VERSION 5.8 ;
BUSBITCHARS "[]" ;
DIVIDERCHAR "/" ;
UNITS
    DATABASE MICRONS 1000 ;
END UNITS

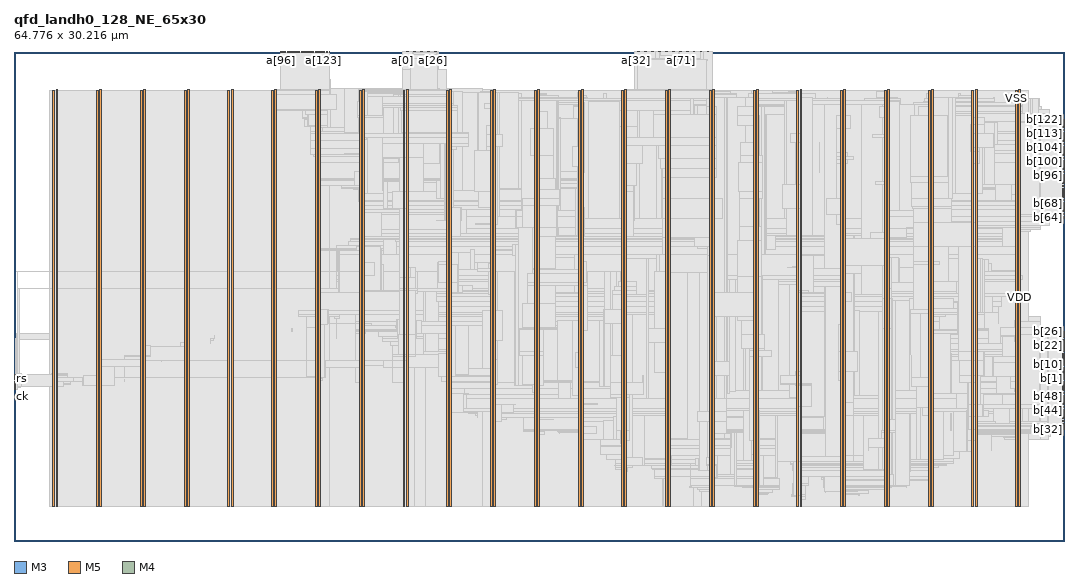
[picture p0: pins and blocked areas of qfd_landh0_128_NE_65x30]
MACRO qfd_landh0_128_NE_65x30
  FOREIGN qfd_landh0_128_NE_65x30 0 0 ;
  CLASS BLOCK ;
  SIZE 64.776 BY 30.216 ;
  PIN a[0]
    DIRECTION INPUT ;
    USE SIGNAL ;
    PORT
      LAYER M3 ;
        RECT  23.94 30.179 23.958 30.216 ;
    END
  END a[0]
  PIN a[100]
    DIRECTION INPUT ;
    USE SIGNAL ;
    PORT
      LAYER M5 ;
        RECT  16.848 30.132 16.872 30.216 ;
    END
  END a[100]
  PIN a[101]
    DIRECTION INPUT ;
    USE SIGNAL ;
    PORT
      LAYER M5 ;
        RECT  16.944 30.132 16.968 30.216 ;
    END
  END a[101]
  PIN a[102]
    DIRECTION INPUT ;
    USE SIGNAL ;
    PORT
      LAYER M5 ;
        RECT  17.04 30.132 17.064 30.216 ;
    END
  END a[102]
  PIN a[103]
    DIRECTION INPUT ;
    USE SIGNAL ;
    PORT
      LAYER M5 ;
        RECT  17.136 30.132 17.16 30.216 ;
    END
  END a[103]
  PIN a[104]
    DIRECTION INPUT ;
    USE SIGNAL ;
    PORT
      LAYER M5 ;
        RECT  17.232 30.132 17.256 30.216 ;
    END
  END a[104]
  PIN a[105]
    DIRECTION INPUT ;
    USE SIGNAL ;
    PORT
      LAYER M5 ;
        RECT  17.328 30.132 17.352 30.216 ;
    END
  END a[105]
  PIN a[106]
    DIRECTION INPUT ;
    USE SIGNAL ;
    PORT
      LAYER M5 ;
        RECT  17.424 30.132 17.448 30.216 ;
    END
  END a[106]
  PIN a[107]
    DIRECTION INPUT ;
    USE SIGNAL ;
    PORT
      LAYER M5 ;
        RECT  17.52 30.132 17.544 30.216 ;
    END
  END a[107]
  PIN a[108]
    DIRECTION INPUT ;
    USE SIGNAL ;
    PORT
      LAYER M5 ;
        RECT  17.616 30.132 17.64 30.216 ;
    END
  END a[108]
  PIN a[109]
    DIRECTION INPUT ;
    USE SIGNAL ;
    PORT
      LAYER M5 ;
        RECT  17.712 30.132 17.736 30.216 ;
    END
  END a[109]
  PIN a[10]
    DIRECTION INPUT ;
    USE SIGNAL ;
    PORT
      LAYER M3 ;
        RECT  24.66 30.179 24.678 30.216 ;
    END
  END a[10]
  PIN a[110]
    DIRECTION INPUT ;
    USE SIGNAL ;
    PORT
      LAYER M5 ;
        RECT  17.808 30.132 17.832 30.216 ;
    END
  END a[110]
  PIN a[111]
    DIRECTION INPUT ;
    USE SIGNAL ;
    PORT
      LAYER M5 ;
        RECT  17.904 30.132 17.928 30.216 ;
    END
  END a[111]
  PIN a[112]
    DIRECTION INPUT ;
    USE SIGNAL ;
    PORT
      LAYER M5 ;
        RECT  18 30.132 18.024 30.216 ;
    END
  END a[112]
  PIN a[113]
    DIRECTION INPUT ;
    USE SIGNAL ;
    PORT
      LAYER M5 ;
        RECT  18.096 30.132 18.12 30.216 ;
    END
  END a[113]
  PIN a[114]
    DIRECTION INPUT ;
    USE SIGNAL ;
    PORT
      LAYER M5 ;
        RECT  18.192 30.132 18.216 30.216 ;
    END
  END a[114]
  PIN a[115]
    DIRECTION INPUT ;
    USE SIGNAL ;
    PORT
      LAYER M5 ;
        RECT  18.288 30.132 18.312 30.216 ;
    END
  END a[115]
  PIN a[116]
    DIRECTION INPUT ;
    USE SIGNAL ;
    PORT
      LAYER M5 ;
        RECT  18.384 30.132 18.408 30.216 ;
    END
  END a[116]
  PIN a[117]
    DIRECTION INPUT ;
    USE SIGNAL ;
    PORT
      LAYER M5 ;
        RECT  18.48 30.132 18.504 30.216 ;
    END
  END a[117]
  PIN a[118]
    DIRECTION INPUT ;
    USE SIGNAL ;
    PORT
      LAYER M5 ;
        RECT  18.576 30.132 18.6 30.216 ;
    END
  END a[118]
  PIN a[119]
    DIRECTION INPUT ;
    USE SIGNAL ;
    PORT
      LAYER M5 ;
        RECT  18.672 30.132 18.696 30.216 ;
    END
  END a[119]
  PIN a[11]
    DIRECTION INPUT ;
    USE SIGNAL ;
    PORT
      LAYER M3 ;
        RECT  24.732 30.179 24.75 30.216 ;
    END
  END a[11]
  PIN a[120]
    DIRECTION INPUT ;
    USE SIGNAL ;
    PORT
      LAYER M5 ;
        RECT  18.768 30.132 18.792 30.216 ;
    END
  END a[120]
  PIN a[121]
    DIRECTION INPUT ;
    USE SIGNAL ;
    PORT
      LAYER M5 ;
        RECT  18.864 30.132 18.888 30.216 ;
    END
  END a[121]
  PIN a[122]
    DIRECTION INPUT ;
    USE SIGNAL ;
    PORT
      LAYER M5 ;
        RECT  18.96 30.132 18.984 30.216 ;
    END
  END a[122]
  PIN a[123]
    DIRECTION INPUT ;
    USE SIGNAL ;
    PORT
      LAYER M5 ;
        RECT  19.056 30.132 19.08 30.216 ;
    END
  END a[123]
  PIN a[124]
    DIRECTION INPUT ;
    USE SIGNAL ;
    PORT
      LAYER M5 ;
        RECT  19.152 30.132 19.176 30.216 ;
    END
  END a[124]
  PIN a[125]
    DIRECTION INPUT ;
    USE SIGNAL ;
    PORT
      LAYER M5 ;
        RECT  19.248 30.132 19.272 30.216 ;
    END
  END a[125]
  PIN a[126]
    DIRECTION INPUT ;
    USE SIGNAL ;
    PORT
      LAYER M5 ;
        RECT  19.344 30.132 19.368 30.216 ;
    END
  END a[126]
  PIN a[127]
    DIRECTION INPUT ;
    USE SIGNAL ;
    PORT
      LAYER M5 ;
        RECT  19.44 30.132 19.464 30.216 ;
    END
  END a[127]
  PIN a[12]
    DIRECTION INPUT ;
    USE SIGNAL ;
    PORT
      LAYER M3 ;
        RECT  24.804 30.179 24.822 30.216 ;
    END
  END a[12]
  PIN a[13]
    DIRECTION INPUT ;
    USE SIGNAL ;
    PORT
      LAYER M3 ;
        RECT  24.876 30.179 24.894 30.216 ;
    END
  END a[13]
  PIN a[14]
    DIRECTION INPUT ;
    USE SIGNAL ;
    PORT
      LAYER M3 ;
        RECT  24.948 30.179 24.966 30.216 ;
    END
  END a[14]
  PIN a[15]
    DIRECTION INPUT ;
    USE SIGNAL ;
    PORT
      LAYER M3 ;
        RECT  25.02 30.179 25.038 30.216 ;
    END
  END a[15]
  PIN a[16]
    DIRECTION INPUT ;
    USE SIGNAL ;
    PORT
      LAYER M3 ;
        RECT  25.092 30.179 25.11 30.216 ;
    END
  END a[16]
  PIN a[17]
    DIRECTION INPUT ;
    USE SIGNAL ;
    PORT
      LAYER M3 ;
        RECT  25.164 30.179 25.182 30.216 ;
    END
  END a[17]
  PIN a[18]
    DIRECTION INPUT ;
    USE SIGNAL ;
    PORT
      LAYER M3 ;
        RECT  25.236 30.179 25.254 30.216 ;
    END
  END a[18]
  PIN a[19]
    DIRECTION INPUT ;
    USE SIGNAL ;
    PORT
      LAYER M3 ;
        RECT  25.308 30.179 25.326 30.216 ;
    END
  END a[19]
  PIN a[1]
    DIRECTION INPUT ;
    USE SIGNAL ;
    PORT
      LAYER M3 ;
        RECT  24.012 30.179 24.03 30.216 ;
    END
  END a[1]
  PIN a[20]
    DIRECTION INPUT ;
    USE SIGNAL ;
    PORT
      LAYER M3 ;
        RECT  25.38 30.179 25.398 30.216 ;
    END
  END a[20]
  PIN a[21]
    DIRECTION INPUT ;
    USE SIGNAL ;
    PORT
      LAYER M3 ;
        RECT  25.452 30.179 25.47 30.216 ;
    END
  END a[21]
  PIN a[22]
    DIRECTION INPUT ;
    USE SIGNAL ;
    PORT
      LAYER M3 ;
        RECT  25.524 30.179 25.542 30.216 ;
    END
  END a[22]
  PIN a[23]
    DIRECTION INPUT ;
    USE SIGNAL ;
    PORT
      LAYER M3 ;
        RECT  25.596 30.179 25.614 30.216 ;
    END
  END a[23]
  PIN a[24]
    DIRECTION INPUT ;
    USE SIGNAL ;
    PORT
      LAYER M3 ;
        RECT  25.668 30.179 25.686 30.216 ;
    END
  END a[24]
  PIN a[25]
    DIRECTION INPUT ;
    USE SIGNAL ;
    PORT
      LAYER M3 ;
        RECT  25.74 30.179 25.758 30.216 ;
    END
  END a[25]
  PIN a[26]
    DIRECTION INPUT ;
    USE SIGNAL ;
    PORT
      LAYER M3 ;
        RECT  25.812 30.179 25.83 30.216 ;
    END
  END a[26]
  PIN a[27]
    DIRECTION INPUT ;
    USE SIGNAL ;
    PORT
      LAYER M3 ;
        RECT  25.884 30.179 25.902 30.216 ;
    END
  END a[27]
  PIN a[28]
    DIRECTION INPUT ;
    USE SIGNAL ;
    PORT
      LAYER M3 ;
        RECT  25.956 30.179 25.974 30.216 ;
    END
  END a[28]
  PIN a[29]
    DIRECTION INPUT ;
    USE SIGNAL ;
    PORT
      LAYER M3 ;
        RECT  26.028 30.179 26.046 30.216 ;
    END
  END a[29]
  PIN a[2]
    DIRECTION INPUT ;
    USE SIGNAL ;
    PORT
      LAYER M3 ;
        RECT  24.084 30.179 24.102 30.216 ;
    END
  END a[2]
  PIN a[30]
    DIRECTION INPUT ;
    USE SIGNAL ;
    PORT
      LAYER M3 ;
        RECT  26.1 30.179 26.118 30.216 ;
    END
  END a[30]
  PIN a[31]
    DIRECTION INPUT ;
    USE SIGNAL ;
    PORT
      LAYER M3 ;
        RECT  26.172 30.179 26.19 30.216 ;
    END
  END a[31]
  PIN a[32]
    DIRECTION INPUT ;
    USE SIGNAL ;
    PORT
      LAYER M3 ;
        RECT  38.34 30.179 38.358 30.216 ;
    END
  END a[32]
  PIN a[33]
    DIRECTION INPUT ;
    USE SIGNAL ;
    PORT
      LAYER M3 ;
        RECT  38.412 30.179 38.43 30.216 ;
    END
  END a[33]
  PIN a[34]
    DIRECTION INPUT ;
    USE SIGNAL ;
    PORT
      LAYER M3 ;
        RECT  38.484 30.179 38.502 30.216 ;
    END
  END a[34]
  PIN a[35]
    DIRECTION INPUT ;
    USE SIGNAL ;
    PORT
      LAYER M3 ;
        RECT  38.556 30.179 38.574 30.216 ;
    END
  END a[35]
  PIN a[36]
    DIRECTION INPUT ;
    USE SIGNAL ;
    PORT
      LAYER M3 ;
        RECT  38.628 30.179 38.646 30.216 ;
    END
  END a[36]
  PIN a[37]
    DIRECTION INPUT ;
    USE SIGNAL ;
    PORT
      LAYER M3 ;
        RECT  38.7 30.179 38.718 30.216 ;
    END
  END a[37]
  PIN a[38]
    DIRECTION INPUT ;
    USE SIGNAL ;
    PORT
      LAYER M3 ;
        RECT  38.772 30.179 38.79 30.216 ;
    END
  END a[38]
  PIN a[39]
    DIRECTION INPUT ;
    USE SIGNAL ;
    PORT
      LAYER M3 ;
        RECT  38.844 30.179 38.862 30.216 ;
    END
  END a[39]
  PIN a[3]
    DIRECTION INPUT ;
    USE SIGNAL ;
    PORT
      LAYER M3 ;
        RECT  24.156 30.179 24.174 30.216 ;
    END
  END a[3]
  PIN a[40]
    DIRECTION INPUT ;
    USE SIGNAL ;
    PORT
      LAYER M3 ;
        RECT  38.916 30.179 38.934 30.216 ;
    END
  END a[40]
  PIN a[41]
    DIRECTION INPUT ;
    USE SIGNAL ;
    PORT
      LAYER M3 ;
        RECT  38.988 30.179 39.006 30.216 ;
    END
  END a[41]
  PIN a[42]
    DIRECTION INPUT ;
    USE SIGNAL ;
    PORT
      LAYER M3 ;
        RECT  39.06 30.179 39.078 30.216 ;
    END
  END a[42]
  PIN a[43]
    DIRECTION INPUT ;
    USE SIGNAL ;
    PORT
      LAYER M3 ;
        RECT  39.132 30.179 39.15 30.216 ;
    END
  END a[43]
  PIN a[44]
    DIRECTION INPUT ;
    USE SIGNAL ;
    PORT
      LAYER M3 ;
        RECT  39.204 30.179 39.222 30.216 ;
    END
  END a[44]
  PIN a[45]
    DIRECTION INPUT ;
    USE SIGNAL ;
    PORT
      LAYER M3 ;
        RECT  39.276 30.179 39.294 30.216 ;
    END
  END a[45]
  PIN a[46]
    DIRECTION INPUT ;
    USE SIGNAL ;
    PORT
      LAYER M3 ;
        RECT  39.348 30.179 39.366 30.216 ;
    END
  END a[46]
  PIN a[47]
    DIRECTION INPUT ;
    USE SIGNAL ;
    PORT
      LAYER M3 ;
        RECT  39.42 30.179 39.438 30.216 ;
    END
  END a[47]
  PIN a[48]
    DIRECTION INPUT ;
    USE SIGNAL ;
    PORT
      LAYER M3 ;
        RECT  39.492 30.179 39.51 30.216 ;
    END
  END a[48]
  PIN a[49]
    DIRECTION INPUT ;
    USE SIGNAL ;
    PORT
      LAYER M3 ;
        RECT  39.564 30.179 39.582 30.216 ;
    END
  END a[49]
  PIN a[4]
    DIRECTION INPUT ;
    USE SIGNAL ;
    PORT
      LAYER M3 ;
        RECT  24.228 30.179 24.246 30.216 ;
    END
  END a[4]
  PIN a[50]
    DIRECTION INPUT ;
    USE SIGNAL ;
    PORT
      LAYER M3 ;
        RECT  39.636 30.179 39.654 30.216 ;
    END
  END a[50]
  PIN a[51]
    DIRECTION INPUT ;
    USE SIGNAL ;
    PORT
      LAYER M3 ;
        RECT  39.708 30.179 39.726 30.216 ;
    END
  END a[51]
  PIN a[52]
    DIRECTION INPUT ;
    USE SIGNAL ;
    PORT
      LAYER M3 ;
        RECT  39.78 30.179 39.798 30.216 ;
    END
  END a[52]
  PIN a[53]
    DIRECTION INPUT ;
    USE SIGNAL ;
    PORT
      LAYER M3 ;
        RECT  39.852 30.179 39.87 30.216 ;
    END
  END a[53]
  PIN a[54]
    DIRECTION INPUT ;
    USE SIGNAL ;
    PORT
      LAYER M3 ;
        RECT  39.924 30.179 39.942 30.216 ;
    END
  END a[54]
  PIN a[55]
    DIRECTION INPUT ;
    USE SIGNAL ;
    PORT
      LAYER M3 ;
        RECT  39.996 30.179 40.014 30.216 ;
    END
  END a[55]
  PIN a[56]
    DIRECTION INPUT ;
    USE SIGNAL ;
    PORT
      LAYER M3 ;
        RECT  40.068 30.179 40.086 30.216 ;
    END
  END a[56]
  PIN a[57]
    DIRECTION INPUT ;
    USE SIGNAL ;
    PORT
      LAYER M3 ;
        RECT  40.14 30.179 40.158 30.216 ;
    END
  END a[57]
  PIN a[58]
    DIRECTION INPUT ;
    USE SIGNAL ;
    PORT
      LAYER M3 ;
        RECT  40.212 30.179 40.23 30.216 ;
    END
  END a[58]
  PIN a[59]
    DIRECTION INPUT ;
    USE SIGNAL ;
    PORT
      LAYER M3 ;
        RECT  40.284 30.179 40.302 30.216 ;
    END
  END a[59]
  PIN a[5]
    DIRECTION INPUT ;
    USE SIGNAL ;
    PORT
      LAYER M3 ;
        RECT  24.3 30.179 24.318 30.216 ;
    END
  END a[5]
  PIN a[60]
    DIRECTION INPUT ;
    USE SIGNAL ;
    PORT
      LAYER M3 ;
        RECT  40.356 30.179 40.374 30.216 ;
    END
  END a[60]
  PIN a[61]
    DIRECTION INPUT ;
    USE SIGNAL ;
    PORT
      LAYER M3 ;
        RECT  40.428 30.179 40.446 30.216 ;
    END
  END a[61]
  PIN a[62]
    DIRECTION INPUT ;
    USE SIGNAL ;
    PORT
      LAYER M3 ;
        RECT  40.5 30.179 40.518 30.216 ;
    END
  END a[62]
  PIN a[63]
    DIRECTION INPUT ;
    USE SIGNAL ;
    PORT
      LAYER M3 ;
        RECT  40.572 30.179 40.59 30.216 ;
    END
  END a[63]
  PIN a[64]
    DIRECTION INPUT ;
    USE SIGNAL ;
    PORT
      LAYER M3 ;
        RECT  40.644 30.179 40.662 30.216 ;
    END
  END a[64]
  PIN a[65]
    DIRECTION INPUT ;
    USE SIGNAL ;
    PORT
      LAYER M3 ;
        RECT  40.716 30.179 40.734 30.216 ;
    END
  END a[65]
  PIN a[66]
    DIRECTION INPUT ;
    USE SIGNAL ;
    PORT
      LAYER M3 ;
        RECT  40.788 30.179 40.806 30.216 ;
    END
  END a[66]
  PIN a[67]
    DIRECTION INPUT ;
    USE SIGNAL ;
    PORT
      LAYER M3 ;
        RECT  40.86 30.179 40.878 30.216 ;
    END
  END a[67]
  PIN a[68]
    DIRECTION INPUT ;
    USE SIGNAL ;
    PORT
      LAYER M3 ;
        RECT  40.932 30.179 40.95 30.216 ;
    END
  END a[68]
  PIN a[69]
    DIRECTION INPUT ;
    USE SIGNAL ;
    PORT
      LAYER M3 ;
        RECT  41.004 30.179 41.022 30.216 ;
    END
  END a[69]
  PIN a[6]
    DIRECTION INPUT ;
    USE SIGNAL ;
    PORT
      LAYER M3 ;
        RECT  24.372 30.179 24.39 30.216 ;
    END
  END a[6]
  PIN a[70]
    DIRECTION INPUT ;
    USE SIGNAL ;
    PORT
      LAYER M3 ;
        RECT  41.076 30.179 41.094 30.216 ;
    END
  END a[70]
  PIN a[71]
    DIRECTION INPUT ;
    USE SIGNAL ;
    PORT
      LAYER M3 ;
        RECT  41.148 30.179 41.166 30.216 ;
    END
  END a[71]
  PIN a[72]
    DIRECTION INPUT ;
    USE SIGNAL ;
    PORT
      LAYER M3 ;
        RECT  41.22 30.179 41.238 30.216 ;
    END
  END a[72]
  PIN a[73]
    DIRECTION INPUT ;
    USE SIGNAL ;
    PORT
      LAYER M3 ;
        RECT  41.292 30.179 41.31 30.216 ;
    END
  END a[73]
  PIN a[74]
    DIRECTION INPUT ;
    USE SIGNAL ;
    PORT
      LAYER M3 ;
        RECT  41.364 30.179 41.382 30.216 ;
    END
  END a[74]
  PIN a[75]
    DIRECTION INPUT ;
    USE SIGNAL ;
    PORT
      LAYER M3 ;
        RECT  41.436 30.179 41.454 30.216 ;
    END
  END a[75]
  PIN a[76]
    DIRECTION INPUT ;
    USE SIGNAL ;
    PORT
      LAYER M3 ;
        RECT  41.508 30.179 41.526 30.216 ;
    END
  END a[76]
  PIN a[77]
    DIRECTION INPUT ;
    USE SIGNAL ;
    PORT
      LAYER M3 ;
        RECT  41.58 30.179 41.598 30.216 ;
    END
  END a[77]
  PIN a[78]
    DIRECTION INPUT ;
    USE SIGNAL ;
    PORT
      LAYER M3 ;
        RECT  41.652 30.179 41.67 30.216 ;
    END
  END a[78]
  PIN a[79]
    DIRECTION INPUT ;
    USE SIGNAL ;
    PORT
      LAYER M3 ;
        RECT  41.724 30.179 41.742 30.216 ;
    END
  END a[79]
  PIN a[7]
    DIRECTION INPUT ;
    USE SIGNAL ;
    PORT
      LAYER M3 ;
        RECT  24.444 30.179 24.462 30.216 ;
    END
  END a[7]
  PIN a[80]
    DIRECTION INPUT ;
    USE SIGNAL ;
    PORT
      LAYER M3 ;
        RECT  41.796 30.179 41.814 30.216 ;
    END
  END a[80]
  PIN a[81]
    DIRECTION INPUT ;
    USE SIGNAL ;
    PORT
      LAYER M3 ;
        RECT  41.868 30.179 41.886 30.216 ;
    END
  END a[81]
  PIN a[82]
    DIRECTION INPUT ;
    USE SIGNAL ;
    PORT
      LAYER M3 ;
        RECT  41.94 30.179 41.958 30.216 ;
    END
  END a[82]
  PIN a[83]
    DIRECTION INPUT ;
    USE SIGNAL ;
    PORT
      LAYER M3 ;
        RECT  42.012 30.179 42.03 30.216 ;
    END
  END a[83]
  PIN a[84]
    DIRECTION INPUT ;
    USE SIGNAL ;
    PORT
      LAYER M3 ;
        RECT  42.084 30.179 42.102 30.216 ;
    END
  END a[84]
  PIN a[85]
    DIRECTION INPUT ;
    USE SIGNAL ;
    PORT
      LAYER M3 ;
        RECT  42.156 30.179 42.174 30.216 ;
    END
  END a[85]
  PIN a[86]
    DIRECTION INPUT ;
    USE SIGNAL ;
    PORT
      LAYER M3 ;
        RECT  42.228 30.179 42.246 30.216 ;
    END
  END a[86]
  PIN a[87]
    DIRECTION INPUT ;
    USE SIGNAL ;
    PORT
      LAYER M3 ;
        RECT  42.3 30.179 42.318 30.216 ;
    END
  END a[87]
  PIN a[88]
    DIRECTION INPUT ;
    USE SIGNAL ;
    PORT
      LAYER M3 ;
        RECT  42.372 30.179 42.39 30.216 ;
    END
  END a[88]
  PIN a[89]
    DIRECTION INPUT ;
    USE SIGNAL ;
    PORT
      LAYER M3 ;
        RECT  42.444 30.179 42.462 30.216 ;
    END
  END a[89]
  PIN a[8]
    DIRECTION INPUT ;
    USE SIGNAL ;
    PORT
      LAYER M3 ;
        RECT  24.516 30.179 24.534 30.216 ;
    END
  END a[8]
  PIN a[90]
    DIRECTION INPUT ;
    USE SIGNAL ;
    PORT
      LAYER M3 ;
        RECT  42.516 30.179 42.534 30.216 ;
    END
  END a[90]
  PIN a[91]
    DIRECTION INPUT ;
    USE SIGNAL ;
    PORT
      LAYER M3 ;
        RECT  42.588 30.179 42.606 30.216 ;
    END
  END a[91]
  PIN a[92]
    DIRECTION INPUT ;
    USE SIGNAL ;
    PORT
      LAYER M3 ;
        RECT  42.66 30.179 42.678 30.216 ;
    END
  END a[92]
  PIN a[93]
    DIRECTION INPUT ;
    USE SIGNAL ;
    PORT
      LAYER M3 ;
        RECT  42.732 30.179 42.75 30.216 ;
    END
  END a[93]
  PIN a[94]
    DIRECTION INPUT ;
    USE SIGNAL ;
    PORT
      LAYER M3 ;
        RECT  42.804 30.179 42.822 30.216 ;
    END
  END a[94]
  PIN a[95]
    DIRECTION INPUT ;
    USE SIGNAL ;
    PORT
      LAYER M3 ;
        RECT  42.876 30.179 42.894 30.216 ;
    END
  END a[95]
  PIN a[96]
    DIRECTION INPUT ;
    USE SIGNAL ;
    PORT
      LAYER M5 ;
        RECT  16.464 30.132 16.488 30.216 ;
    END
  END a[96]
  PIN a[97]
    DIRECTION INPUT ;
    USE SIGNAL ;
    PORT
      LAYER M5 ;
        RECT  16.56 30.132 16.584 30.216 ;
    END
  END a[97]
  PIN a[98]
    DIRECTION INPUT ;
    USE SIGNAL ;
    PORT
      LAYER M5 ;
        RECT  16.656 30.132 16.68 30.216 ;
    END
  END a[98]
  PIN a[99]
    DIRECTION INPUT ;
    USE SIGNAL ;
    PORT
      LAYER M5 ;
        RECT  16.752 30.132 16.776 30.216 ;
    END
  END a[99]
  PIN a[9]
    DIRECTION INPUT ;
    USE SIGNAL ;
    PORT
      LAYER M3 ;
        RECT  24.588 30.179 24.606 30.216 ;
    END
  END a[9]
  PIN b[0]
    DIRECTION OUTPUT ;
    USE SIGNAL ;
    PORT
      LAYER M4 ;
        RECT  64.692 9.936 64.776 9.96 ;
    END
  END b[0]
  PIN b[100]
    DIRECTION OUTPUT ;
    USE SIGNAL ;
    PORT
      LAYER M4 ;
        RECT  64.692 23.376 64.776 23.4 ;
    END
  END b[100]
  PIN b[101]
    DIRECTION OUTPUT ;
    USE SIGNAL ;
    PORT
      LAYER M4 ;
        RECT  64.692 23.472 64.776 23.496 ;
    END
  END b[101]
  PIN b[102]
    DIRECTION OUTPUT ;
    USE SIGNAL ;
    PORT
      LAYER M4 ;
        RECT  64.692 23.568 64.776 23.592 ;
    END
  END b[102]
  PIN b[103]
    DIRECTION OUTPUT ;
    USE SIGNAL ;
    PORT
      LAYER M4 ;
        RECT  64.692 23.664 64.776 23.688 ;
    END
  END b[103]
  PIN b[104]
    DIRECTION OUTPUT ;
    USE SIGNAL ;
    PORT
      LAYER M4 ;
        RECT  64.692 23.76 64.776 23.784 ;
    END
  END b[104]
  PIN b[105]
    DIRECTION OUTPUT ;
    USE SIGNAL ;
    PORT
      LAYER M4 ;
        RECT  64.692 23.856 64.776 23.88 ;
    END
  END b[105]
  PIN b[106]
    DIRECTION OUTPUT ;
    USE SIGNAL ;
    PORT
      LAYER M4 ;
        RECT  64.692 23.952 64.776 23.976 ;
    END
  END b[106]
  PIN b[107]
    DIRECTION OUTPUT ;
    USE SIGNAL ;
    PORT
      LAYER M4 ;
        RECT  64.692 24.048 64.776 24.072 ;
    END
  END b[107]
  PIN b[108]
    DIRECTION OUTPUT ;
    USE SIGNAL ;
    PORT
      LAYER M4 ;
        RECT  64.692 24.144 64.776 24.168 ;
    END
  END b[108]
  PIN b[109]
    DIRECTION OUTPUT ;
    USE SIGNAL ;
    PORT
      LAYER M4 ;
        RECT  64.692 24.24 64.776 24.264 ;
    END
  END b[109]
  PIN b[10]
    DIRECTION OUTPUT ;
    USE SIGNAL ;
    PORT
      LAYER M4 ;
        RECT  64.692 10.896 64.776 10.92 ;
    END
  END b[10]
  PIN b[110]
    DIRECTION OUTPUT ;
    USE SIGNAL ;
    PORT
      LAYER M4 ;
        RECT  64.692 24.336 64.776 24.36 ;
    END
  END b[110]
  PIN b[111]
    DIRECTION OUTPUT ;
    USE SIGNAL ;
    PORT
      LAYER M4 ;
        RECT  64.692 24.432 64.776 24.456 ;
    END
  END b[111]
  PIN b[112]
    DIRECTION OUTPUT ;
    USE SIGNAL ;
    PORT
      LAYER M4 ;
        RECT  64.692 24.528 64.776 24.552 ;
    END
  END b[112]
  PIN b[113]
    DIRECTION OUTPUT ;
    USE SIGNAL ;
    PORT
      LAYER M4 ;
        RECT  64.692 24.624 64.776 24.648 ;
    END
  END b[113]
  PIN b[114]
    DIRECTION OUTPUT ;
    USE SIGNAL ;
    PORT
      LAYER M4 ;
        RECT  64.692 24.72 64.776 24.744 ;
    END
  END b[114]
  PIN b[115]
    DIRECTION OUTPUT ;
    USE SIGNAL ;
    PORT
      LAYER M4 ;
        RECT  64.692 24.816 64.776 24.84 ;
    END
  END b[115]
  PIN b[116]
    DIRECTION OUTPUT ;
    USE SIGNAL ;
    PORT
      LAYER M4 ;
        RECT  64.692 24.912 64.776 24.936 ;
    END
  END b[116]
  PIN b[117]
    DIRECTION OUTPUT ;
    USE SIGNAL ;
    PORT
      LAYER M4 ;
        RECT  64.692 25.008 64.776 25.032 ;
    END
  END b[117]
  PIN b[118]
    DIRECTION OUTPUT ;
    USE SIGNAL ;
    PORT
      LAYER M4 ;
        RECT  64.692 25.104 64.776 25.128 ;
    END
  END b[118]
  PIN b[119]
    DIRECTION OUTPUT ;
    USE SIGNAL ;
    PORT
      LAYER M4 ;
        RECT  64.692 25.2 64.776 25.224 ;
    END
  END b[119]
  PIN b[11]
    DIRECTION OUTPUT ;
    USE SIGNAL ;
    PORT
      LAYER M4 ;
        RECT  64.692 10.992 64.776 11.016 ;
    END
  END b[11]
  PIN b[120]
    DIRECTION OUTPUT ;
    USE SIGNAL ;
    PORT
      LAYER M4 ;
        RECT  64.692 25.296 64.776 25.32 ;
    END
  END b[120]
  PIN b[121]
    DIRECTION OUTPUT ;
    USE SIGNAL ;
    PORT
      LAYER M4 ;
        RECT  64.692 25.392 64.776 25.416 ;
    END
  END b[121]
  PIN b[122]
    DIRECTION OUTPUT ;
    USE SIGNAL ;
    PORT
      LAYER M4 ;
        RECT  64.692 25.488 64.776 25.512 ;
    END
  END b[122]
  PIN b[123]
    DIRECTION OUTPUT ;
    USE SIGNAL ;
    PORT
      LAYER M4 ;
        RECT  64.692 25.584 64.776 25.608 ;
    END
  END b[123]
  PIN b[124]
    DIRECTION OUTPUT ;
    USE SIGNAL ;
    PORT
      LAYER M4 ;
        RECT  64.692 25.68 64.776 25.704 ;
    END
  END b[124]
  PIN b[125]
    DIRECTION OUTPUT ;
    USE SIGNAL ;
    PORT
      LAYER M4 ;
        RECT  64.692 25.776 64.776 25.8 ;
    END
  END b[125]
  PIN b[126]
    DIRECTION OUTPUT ;
    USE SIGNAL ;
    PORT
      LAYER M4 ;
        RECT  64.692 25.872 64.776 25.896 ;
    END
  END b[126]
  PIN b[127]
    DIRECTION OUTPUT ;
    USE SIGNAL ;
    PORT
      LAYER M4 ;
        RECT  64.692 25.968 64.776 25.992 ;
    END
  END b[127]
  PIN b[12]
    DIRECTION OUTPUT ;
    USE SIGNAL ;
    PORT
      LAYER M4 ;
        RECT  64.692 11.088 64.776 11.112 ;
    END
  END b[12]
  PIN b[13]
    DIRECTION OUTPUT ;
    USE SIGNAL ;
    PORT
      LAYER M4 ;
        RECT  64.692 11.184 64.776 11.208 ;
    END
  END b[13]
  PIN b[14]
    DIRECTION OUTPUT ;
    USE SIGNAL ;
    PORT
      LAYER M4 ;
        RECT  64.692 11.28 64.776 11.304 ;
    END
  END b[14]
  PIN b[15]
    DIRECTION OUTPUT ;
    USE SIGNAL ;
    PORT
      LAYER M4 ;
        RECT  64.692 11.376 64.776 11.4 ;
    END
  END b[15]
  PIN b[16]
    DIRECTION OUTPUT ;
    USE SIGNAL ;
    PORT
      LAYER M4 ;
        RECT  64.692 11.472 64.776 11.496 ;
    END
  END b[16]
  PIN b[17]
    DIRECTION OUTPUT ;
    USE SIGNAL ;
    PORT
      LAYER M4 ;
        RECT  64.692 11.568 64.776 11.592 ;
    END
  END b[17]
  PIN b[18]
    DIRECTION OUTPUT ;
    USE SIGNAL ;
    PORT
      LAYER M4 ;
        RECT  64.692 11.664 64.776 11.688 ;
    END
  END b[18]
  PIN b[19]
    DIRECTION OUTPUT ;
    USE SIGNAL ;
    PORT
      LAYER M4 ;
        RECT  64.692 11.76 64.776 11.784 ;
    END
  END b[19]
  PIN b[1]
    DIRECTION OUTPUT ;
    USE SIGNAL ;
    PORT
      LAYER M4 ;
        RECT  64.692 10.032 64.776 10.056 ;
    END
  END b[1]
  PIN b[20]
    DIRECTION OUTPUT ;
    USE SIGNAL ;
    PORT
      LAYER M4 ;
        RECT  64.692 11.856 64.776 11.88 ;
    END
  END b[20]
  PIN b[21]
    DIRECTION OUTPUT ;
    USE SIGNAL ;
    PORT
      LAYER M4 ;
        RECT  64.692 11.952 64.776 11.976 ;
    END
  END b[21]
  PIN b[22]
    DIRECTION OUTPUT ;
    USE SIGNAL ;
    PORT
      LAYER M4 ;
        RECT  64.692 12.048 64.776 12.072 ;
    END
  END b[22]
  PIN b[23]
    DIRECTION OUTPUT ;
    USE SIGNAL ;
    PORT
      LAYER M4 ;
        RECT  64.692 12.144 64.776 12.168 ;
    END
  END b[23]
  PIN b[24]
    DIRECTION OUTPUT ;
    USE SIGNAL ;
    PORT
      LAYER M4 ;
        RECT  64.692 12.24 64.776 12.264 ;
    END
  END b[24]
  PIN b[25]
    DIRECTION OUTPUT ;
    USE SIGNAL ;
    PORT
      LAYER M4 ;
        RECT  64.692 12.336 64.776 12.36 ;
    END
  END b[25]
  PIN b[26]
    DIRECTION OUTPUT ;
    USE SIGNAL ;
    PORT
      LAYER M4 ;
        RECT  64.692 12.432 64.776 12.456 ;
    END
  END b[26]
  PIN b[27]
    DIRECTION OUTPUT ;
    USE SIGNAL ;
    PORT
      LAYER M4 ;
        RECT  64.692 12.528 64.776 12.552 ;
    END
  END b[27]
  PIN b[28]
    DIRECTION OUTPUT ;
    USE SIGNAL ;
    PORT
      LAYER M4 ;
        RECT  64.692 12.624 64.776 12.648 ;
    END
  END b[28]
  PIN b[29]
    DIRECTION OUTPUT ;
    USE SIGNAL ;
    PORT
      LAYER M4 ;
        RECT  64.692 12.72 64.776 12.744 ;
    END
  END b[29]
  PIN b[2]
    DIRECTION OUTPUT ;
    USE SIGNAL ;
    PORT
      LAYER M4 ;
        RECT  64.692 10.128 64.776 10.152 ;
    END
  END b[2]
  PIN b[30]
    DIRECTION OUTPUT ;
    USE SIGNAL ;
    PORT
      LAYER M4 ;
        RECT  64.692 12.816 64.776 12.84 ;
    END
  END b[30]
  PIN b[31]
    DIRECTION OUTPUT ;
    USE SIGNAL ;
    PORT
      LAYER M4 ;
        RECT  64.692 12.912 64.776 12.936 ;
    END
  END b[31]
  PIN b[32]
    DIRECTION OUTPUT ;
    USE SIGNAL ;
    PORT
      LAYER M4 ;
        RECT  64.692 6.864 64.776 6.888 ;
    END
  END b[32]
  PIN b[33]
    DIRECTION OUTPUT ;
    USE SIGNAL ;
    PORT
      LAYER M4 ;
        RECT  64.692 6.96 64.776 6.984 ;
    END
  END b[33]
  PIN b[34]
    DIRECTION OUTPUT ;
    USE SIGNAL ;
    PORT
      LAYER M4 ;
        RECT  64.692 7.056 64.776 7.08 ;
    END
  END b[34]
  PIN b[35]
    DIRECTION OUTPUT ;
    USE SIGNAL ;
    PORT
      LAYER M4 ;
        RECT  64.692 7.152 64.776 7.176 ;
    END
  END b[35]
  PIN b[36]
    DIRECTION OUTPUT ;
    USE SIGNAL ;
    PORT
      LAYER M4 ;
        RECT  64.692 7.248 64.776 7.272 ;
    END
  END b[36]
  PIN b[37]
    DIRECTION OUTPUT ;
    USE SIGNAL ;
    PORT
      LAYER M4 ;
        RECT  64.692 7.344 64.776 7.368 ;
    END
  END b[37]
  PIN b[38]
    DIRECTION OUTPUT ;
    USE SIGNAL ;
    PORT
      LAYER M4 ;
        RECT  64.692 7.44 64.776 7.464 ;
    END
  END b[38]
  PIN b[39]
    DIRECTION OUTPUT ;
    USE SIGNAL ;
    PORT
      LAYER M4 ;
        RECT  64.692 7.536 64.776 7.56 ;
    END
  END b[39]
  PIN b[3]
    DIRECTION OUTPUT ;
    USE SIGNAL ;
    PORT
      LAYER M4 ;
        RECT  64.692 10.224 64.776 10.248 ;
    END
  END b[3]
  PIN b[40]
    DIRECTION OUTPUT ;
    USE SIGNAL ;
    PORT
      LAYER M4 ;
        RECT  64.692 7.632 64.776 7.656 ;
    END
  END b[40]
  PIN b[41]
    DIRECTION OUTPUT ;
    USE SIGNAL ;
    PORT
      LAYER M4 ;
        RECT  64.692 7.728 64.776 7.752 ;
    END
  END b[41]
  PIN b[42]
    DIRECTION OUTPUT ;
    USE SIGNAL ;
    PORT
      LAYER M4 ;
        RECT  64.692 7.824 64.776 7.848 ;
    END
  END b[42]
  PIN b[43]
    DIRECTION OUTPUT ;
    USE SIGNAL ;
    PORT
      LAYER M4 ;
        RECT  64.692 7.92 64.776 7.944 ;
    END
  END b[43]
  PIN b[44]
    DIRECTION OUTPUT ;
    USE SIGNAL ;
    PORT
      LAYER M4 ;
        RECT  64.692 8.016 64.776 8.04 ;
    END
  END b[44]
  PIN b[45]
    DIRECTION OUTPUT ;
    USE SIGNAL ;
    PORT
      LAYER M4 ;
        RECT  64.692 8.112 64.776 8.136 ;
    END
  END b[45]
  PIN b[46]
    DIRECTION OUTPUT ;
    USE SIGNAL ;
    PORT
      LAYER M4 ;
        RECT  64.692 8.208 64.776 8.232 ;
    END
  END b[46]
  PIN b[47]
    DIRECTION OUTPUT ;
    USE SIGNAL ;
    PORT
      LAYER M4 ;
        RECT  64.692 8.304 64.776 8.328 ;
    END
  END b[47]
  PIN b[48]
    DIRECTION OUTPUT ;
    USE SIGNAL ;
    PORT
      LAYER M4 ;
        RECT  64.692 8.4 64.776 8.424 ;
    END
  END b[48]
  PIN b[49]
    DIRECTION OUTPUT ;
    USE SIGNAL ;
    PORT
      LAYER M4 ;
        RECT  64.692 8.496 64.776 8.52 ;
    END
  END b[49]
  PIN b[4]
    DIRECTION OUTPUT ;
    USE SIGNAL ;
    PORT
      LAYER M4 ;
        RECT  64.692 10.32 64.776 10.344 ;
    END
  END b[4]
  PIN b[50]
    DIRECTION OUTPUT ;
    USE SIGNAL ;
    PORT
      LAYER M4 ;
        RECT  64.692 8.592 64.776 8.616 ;
    END
  END b[50]
  PIN b[51]
    DIRECTION OUTPUT ;
    USE SIGNAL ;
    PORT
      LAYER M4 ;
        RECT  64.692 8.688 64.776 8.712 ;
    END
  END b[51]
  PIN b[52]
    DIRECTION OUTPUT ;
    USE SIGNAL ;
    PORT
      LAYER M4 ;
        RECT  64.692 8.784 64.776 8.808 ;
    END
  END b[52]
  PIN b[53]
    DIRECTION OUTPUT ;
    USE SIGNAL ;
    PORT
      LAYER M4 ;
        RECT  64.692 8.88 64.776 8.904 ;
    END
  END b[53]
  PIN b[54]
    DIRECTION OUTPUT ;
    USE SIGNAL ;
    PORT
      LAYER M4 ;
        RECT  64.692 8.976 64.776 9 ;
    END
  END b[54]
  PIN b[55]
    DIRECTION OUTPUT ;
    USE SIGNAL ;
    PORT
      LAYER M4 ;
        RECT  64.692 9.072 64.776 9.096 ;
    END
  END b[55]
  PIN b[56]
    DIRECTION OUTPUT ;
    USE SIGNAL ;
    PORT
      LAYER M4 ;
        RECT  64.692 9.168 64.776 9.192 ;
    END
  END b[56]
  PIN b[57]
    DIRECTION OUTPUT ;
    USE SIGNAL ;
    PORT
      LAYER M4 ;
        RECT  64.692 9.264 64.776 9.288 ;
    END
  END b[57]
  PIN b[58]
    DIRECTION OUTPUT ;
    USE SIGNAL ;
    PORT
      LAYER M4 ;
        RECT  64.692 9.36 64.776 9.384 ;
    END
  END b[58]
  PIN b[59]
    DIRECTION OUTPUT ;
    USE SIGNAL ;
    PORT
      LAYER M4 ;
        RECT  64.692 9.456 64.776 9.48 ;
    END
  END b[59]
  PIN b[5]
    DIRECTION OUTPUT ;
    USE SIGNAL ;
    PORT
      LAYER M4 ;
        RECT  64.692 10.416 64.776 10.44 ;
    END
  END b[5]
  PIN b[60]
    DIRECTION OUTPUT ;
    USE SIGNAL ;
    PORT
      LAYER M4 ;
        RECT  64.692 9.552 64.776 9.576 ;
    END
  END b[60]
  PIN b[61]
    DIRECTION OUTPUT ;
    USE SIGNAL ;
    PORT
      LAYER M4 ;
        RECT  64.692 9.648 64.776 9.672 ;
    END
  END b[61]
  PIN b[62]
    DIRECTION OUTPUT ;
    USE SIGNAL ;
    PORT
      LAYER M4 ;
        RECT  64.692 9.744 64.776 9.768 ;
    END
  END b[62]
  PIN b[63]
    DIRECTION OUTPUT ;
    USE SIGNAL ;
    PORT
      LAYER M4 ;
        RECT  64.692 9.84 64.776 9.864 ;
    END
  END b[63]
  PIN b[64]
    DIRECTION OUTPUT ;
    USE SIGNAL ;
    PORT
      LAYER M4 ;
        RECT  64.692 19.92 64.776 19.944 ;
    END
  END b[64]
  PIN b[65]
    DIRECTION OUTPUT ;
    USE SIGNAL ;
    PORT
      LAYER M4 ;
        RECT  64.692 20.016 64.776 20.04 ;
    END
  END b[65]
  PIN b[66]
    DIRECTION OUTPUT ;
    USE SIGNAL ;
    PORT
      LAYER M4 ;
        RECT  64.692 20.112 64.776 20.136 ;
    END
  END b[66]
  PIN b[67]
    DIRECTION OUTPUT ;
    USE SIGNAL ;
    PORT
      LAYER M4 ;
        RECT  64.692 20.208 64.776 20.232 ;
    END
  END b[67]
  PIN b[68]
    DIRECTION OUTPUT ;
    USE SIGNAL ;
    PORT
      LAYER M4 ;
        RECT  64.692 20.304 64.776 20.328 ;
    END
  END b[68]
  PIN b[69]
    DIRECTION OUTPUT ;
    USE SIGNAL ;
    PORT
      LAYER M4 ;
        RECT  64.692 20.4 64.776 20.424 ;
    END
  END b[69]
  PIN b[6]
    DIRECTION OUTPUT ;
    USE SIGNAL ;
    PORT
      LAYER M4 ;
        RECT  64.692 10.512 64.776 10.536 ;
    END
  END b[6]
  PIN b[70]
    DIRECTION OUTPUT ;
    USE SIGNAL ;
    PORT
      LAYER M4 ;
        RECT  64.692 20.496 64.776 20.52 ;
    END
  END b[70]
  PIN b[71]
    DIRECTION OUTPUT ;
    USE SIGNAL ;
    PORT
      LAYER M4 ;
        RECT  64.692 20.592 64.776 20.616 ;
    END
  END b[71]
  PIN b[72]
    DIRECTION OUTPUT ;
    USE SIGNAL ;
    PORT
      LAYER M4 ;
        RECT  64.692 20.688 64.776 20.712 ;
    END
  END b[72]
  PIN b[73]
    DIRECTION OUTPUT ;
    USE SIGNAL ;
    PORT
      LAYER M4 ;
        RECT  64.692 20.784 64.776 20.808 ;
    END
  END b[73]
  PIN b[74]
    DIRECTION OUTPUT ;
    USE SIGNAL ;
    PORT
      LAYER M4 ;
        RECT  64.692 20.88 64.776 20.904 ;
    END
  END b[74]
  PIN b[75]
    DIRECTION OUTPUT ;
    USE SIGNAL ;
    PORT
      LAYER M4 ;
        RECT  64.692 20.976 64.776 21 ;
    END
  END b[75]
  PIN b[76]
    DIRECTION OUTPUT ;
    USE SIGNAL ;
    PORT
      LAYER M4 ;
        RECT  64.692 21.072 64.776 21.096 ;
    END
  END b[76]
  PIN b[77]
    DIRECTION OUTPUT ;
    USE SIGNAL ;
    PORT
      LAYER M4 ;
        RECT  64.692 21.168 64.776 21.192 ;
    END
  END b[77]
  PIN b[78]
    DIRECTION OUTPUT ;
    USE SIGNAL ;
    PORT
      LAYER M4 ;
        RECT  64.692 21.264 64.776 21.288 ;
    END
  END b[78]
  PIN b[79]
    DIRECTION OUTPUT ;
    USE SIGNAL ;
    PORT
      LAYER M4 ;
        RECT  64.692 21.36 64.776 21.384 ;
    END
  END b[79]
  PIN b[7]
    DIRECTION OUTPUT ;
    USE SIGNAL ;
    PORT
      LAYER M4 ;
        RECT  64.692 10.608 64.776 10.632 ;
    END
  END b[7]
  PIN b[80]
    DIRECTION OUTPUT ;
    USE SIGNAL ;
    PORT
      LAYER M4 ;
        RECT  64.692 21.456 64.776 21.48 ;
    END
  END b[80]
  PIN b[81]
    DIRECTION OUTPUT ;
    USE SIGNAL ;
    PORT
      LAYER M4 ;
        RECT  64.692 21.552 64.776 21.576 ;
    END
  END b[81]
  PIN b[82]
    DIRECTION OUTPUT ;
    USE SIGNAL ;
    PORT
      LAYER M4 ;
        RECT  64.692 21.648 64.776 21.672 ;
    END
  END b[82]
  PIN b[83]
    DIRECTION OUTPUT ;
    USE SIGNAL ;
    PORT
      LAYER M4 ;
        RECT  64.692 21.744 64.776 21.768 ;
    END
  END b[83]
  PIN b[84]
    DIRECTION OUTPUT ;
    USE SIGNAL ;
    PORT
      LAYER M4 ;
        RECT  64.692 21.84 64.776 21.864 ;
    END
  END b[84]
  PIN b[85]
    DIRECTION OUTPUT ;
    USE SIGNAL ;
    PORT
      LAYER M4 ;
        RECT  64.692 21.936 64.776 21.96 ;
    END
  END b[85]
  PIN b[86]
    DIRECTION OUTPUT ;
    USE SIGNAL ;
    PORT
      LAYER M4 ;
        RECT  64.692 22.032 64.776 22.056 ;
    END
  END b[86]
  PIN b[87]
    DIRECTION OUTPUT ;
    USE SIGNAL ;
    PORT
      LAYER M4 ;
        RECT  64.692 22.128 64.776 22.152 ;
    END
  END b[87]
  PIN b[88]
    DIRECTION OUTPUT ;
    USE SIGNAL ;
    PORT
      LAYER M4 ;
        RECT  64.692 22.224 64.776 22.248 ;
    END
  END b[88]
  PIN b[89]
    DIRECTION OUTPUT ;
    USE SIGNAL ;
    PORT
      LAYER M4 ;
        RECT  64.692 22.32 64.776 22.344 ;
    END
  END b[89]
  PIN b[8]
    DIRECTION OUTPUT ;
    USE SIGNAL ;
    PORT
      LAYER M4 ;
        RECT  64.692 10.704 64.776 10.728 ;
    END
  END b[8]
  PIN b[90]
    DIRECTION OUTPUT ;
    USE SIGNAL ;
    PORT
      LAYER M4 ;
        RECT  64.692 22.416 64.776 22.44 ;
    END
  END b[90]
  PIN b[91]
    DIRECTION OUTPUT ;
    USE SIGNAL ;
    PORT
      LAYER M4 ;
        RECT  64.692 22.512 64.776 22.536 ;
    END
  END b[91]
  PIN b[92]
    DIRECTION OUTPUT ;
    USE SIGNAL ;
    PORT
      LAYER M4 ;
        RECT  64.692 22.608 64.776 22.632 ;
    END
  END b[92]
  PIN b[93]
    DIRECTION OUTPUT ;
    USE SIGNAL ;
    PORT
      LAYER M4 ;
        RECT  64.692 22.704 64.776 22.728 ;
    END
  END b[93]
  PIN b[94]
    DIRECTION OUTPUT ;
    USE SIGNAL ;
    PORT
      LAYER M4 ;
        RECT  64.692 22.8 64.776 22.824 ;
    END
  END b[94]
  PIN b[95]
    DIRECTION OUTPUT ;
    USE SIGNAL ;
    PORT
      LAYER M4 ;
        RECT  64.692 22.896 64.776 22.92 ;
    END
  END b[95]
  PIN b[96]
    DIRECTION OUTPUT ;
    USE SIGNAL ;
    PORT
      LAYER M4 ;
        RECT  64.692 22.992 64.776 23.016 ;
    END
  END b[96]
  PIN b[97]
    DIRECTION OUTPUT ;
    USE SIGNAL ;
    PORT
      LAYER M4 ;
        RECT  64.692 23.088 64.776 23.112 ;
    END
  END b[97]
  PIN b[98]
    DIRECTION OUTPUT ;
    USE SIGNAL ;
    PORT
      LAYER M4 ;
        RECT  64.692 23.184 64.776 23.208 ;
    END
  END b[98]
  PIN b[99]
    DIRECTION OUTPUT ;
    USE SIGNAL ;
    PORT
      LAYER M4 ;
        RECT  64.692 23.28 64.776 23.304 ;
    END
  END b[99]
  PIN b[9]
    DIRECTION OUTPUT ;
    USE SIGNAL ;
    PORT
      LAYER M4 ;
        RECT  64.692 10.8 64.776 10.824 ;
    END
  END b[9]
  PIN ck
    DIRECTION INPUT ;
    USE SIGNAL ;
    PORT
      LAYER M4 ;
        RECT  0 9.36 0.084 9.384 ;
    END
  END ck
  PIN ck_s
    DIRECTION INPUT ;
    USE SIGNAL ;
    PORT
      LAYER M4 ;
        RECT  0 9.456 0.084 9.48 ;
    END
  END ck_s
  PIN en
    DIRECTION INPUT ;
    USE SIGNAL ;
    PORT
      LAYER M4 ;
        RECT  0 9.552 0.084 9.576 ;
    END
  END en
  PIN fault
    DIRECTION OUTPUT ;
    USE SIGNAL ;
    PORT
      LAYER M4 ;
        RECT  0 9.648 0.084 9.672 ;
    END
  END fault
  PIN k0
    DIRECTION INPUT ;
    USE SIGNAL ;
    PORT
      LAYER M4 ;
        RECT  0 9.744 0.084 9.768 ;
    END
  END k0
  PIN k1
    DIRECTION INPUT ;
    USE SIGNAL ;
    PORT
      LAYER M4 ;
        RECT  0 9.84 0.084 9.864 ;
    END
  END k1
  PIN k2
    DIRECTION INPUT ;
    USE SIGNAL ;
    PORT
      LAYER M4 ;
        RECT  0 9.936 0.084 9.96 ;
    END
  END k2
  PIN rs
    DIRECTION INPUT ;
    USE SIGNAL ;
    PORT
      LAYER M4 ;
        RECT  0 10.032 0.084 10.056 ;
    END
  END rs
  PIN tie_hi
    DIRECTION OUTPUT ;
    USE SIGNAL ;
    PORT
      LAYER M4 ;
        RECT  0 10.128 0.084 10.152 ;
    END
  END tie_hi
  PIN tie_lo
    DIRECTION OUTPUT ;
    USE SIGNAL ;
    PORT
      LAYER M4 ;
        RECT  0 10.224 0.084 10.248 ;
    END
  END tie_lo
  PIN VDD
    DIRECTION INOUT ;
    USE POWER ;
    PORT
      LAYER M5 ;
        RECT  61.992 2.151 62.112 27.833 ;
        RECT  59.292 2.151 59.412 27.833 ;
        RECT  56.592 2.151 56.712 27.833 ;
        RECT  53.892 2.151 54.012 27.833 ;
        RECT  51.192 2.151 51.312 27.833 ;
        RECT  48.492 2.151 48.612 27.833 ;
        RECT  45.792 2.151 45.912 27.833 ;
        RECT  43.092 2.151 43.212 27.833 ;
        RECT  40.392 2.151 40.512 27.833 ;
        RECT  37.692 2.151 37.812 27.833 ;
        RECT  34.992 2.151 35.112 27.833 ;
        RECT  32.292 2.151 32.412 27.833 ;
        RECT  29.592 2.151 29.712 27.833 ;
        RECT  26.892 2.151 27.012 27.833 ;
        RECT  24.192 2.151 24.312 27.833 ;
        RECT  21.492 2.151 21.612 27.833 ;
        RECT  18.792 2.151 18.912 27.833 ;
        RECT  16.092 2.151 16.212 27.833 ;
        RECT  13.392 2.151 13.512 27.833 ;
        RECT  10.692 2.151 10.812 27.833 ;
        RECT  7.992 2.151 8.112 27.833 ;
        RECT  5.292 2.151 5.412 27.833 ;
        RECT  2.592 2.151 2.712 27.833 ;
    END
  END VDD
  PIN VSS
    DIRECTION INOUT ;
    USE GROUND ;
    PORT
      LAYER M5 ;
        RECT  61.8 2.137 61.92 27.819 ;
        RECT  59.1 2.137 59.22 27.819 ;
        RECT  56.4 2.137 56.52 27.819 ;
        RECT  53.7 2.137 53.82 27.819 ;
        RECT  51 2.137 51.12 27.819 ;
        RECT  48.3 2.137 48.42 27.819 ;
        RECT  45.6 2.137 45.72 27.819 ;
        RECT  42.9 2.137 43.02 27.819 ;
        RECT  40.2 2.137 40.32 27.819 ;
        RECT  37.5 2.137 37.62 27.819 ;
        RECT  34.8 2.137 34.92 27.819 ;
        RECT  32.1 2.137 32.22 27.819 ;
        RECT  29.4 2.137 29.52 27.819 ;
        RECT  26.7 2.137 26.82 27.819 ;
        RECT  24 2.137 24.12 27.819 ;
        RECT  21.3 2.137 21.42 27.819 ;
        RECT  18.6 2.137 18.72 27.819 ;
        RECT  15.9 2.137 16.02 27.819 ;
        RECT  13.2 2.137 13.32 27.819 ;
        RECT  10.5 2.137 10.62 27.819 ;
        RECT  7.8 2.137 7.92 27.819 ;
        RECT  5.1 2.137 5.22 27.819 ;
        RECT  2.4 2.137 2.52 27.819 ;
    END
  END VSS
  OBS
    LAYER RVTN ;
     RECT  2.16 2.16 62.586 2.295 ;
     RECT  2.16 2.565 62.586 2.835 ;
     RECT  2.16 3.105 62.586 3.375 ;
     RECT  2.16 3.645 62.586 3.915 ;
     RECT  2.16 4.185 62.586 4.455 ;
     RECT  2.16 4.725 62.586 4.995 ;
     RECT  2.16 5.265 62.586 5.535 ;
     RECT  2.16 5.805 62.586 6.075 ;
     RECT  2.16 6.345 62.586 6.615 ;
     RECT  2.16 6.885 62.586 7.155 ;
     RECT  2.16 7.425 62.586 7.695 ;
     RECT  2.16 7.965 62.586 8.235 ;
     RECT  2.16 8.505 62.586 8.775 ;
     RECT  2.16 9.045 62.586 9.315 ;
     RECT  2.16 9.585 62.586 9.855 ;
     RECT  2.16 10.125 62.586 10.395 ;
     RECT  2.16 10.665 62.586 10.935 ;
     RECT  2.16 11.205 62.586 11.475 ;
     RECT  2.16 11.745 62.586 12.015 ;
     RECT  2.16 12.285 62.586 12.555 ;
     RECT  2.16 12.825 62.586 13.095 ;
     RECT  2.16 13.365 62.586 13.635 ;
     RECT  2.16 13.905 62.586 14.175 ;
     RECT  2.16 14.445 62.586 14.715 ;
     RECT  2.16 14.985 62.586 15.255 ;
     RECT  2.16 15.525 62.586 15.795 ;
     RECT  2.16 16.065 62.586 16.335 ;
     RECT  2.16 16.605 62.586 16.875 ;
     RECT  2.16 17.145 62.586 17.415 ;
     RECT  2.16 17.685 62.586 17.955 ;
     RECT  2.16 18.225 62.586 18.495 ;
     RECT  2.16 18.765 62.586 19.035 ;
     RECT  2.16 19.305 62.586 19.575 ;
     RECT  2.16 19.845 62.586 20.115 ;
     RECT  2.16 20.385 62.586 20.655 ;
     RECT  2.16 20.925 62.586 21.195 ;
     RECT  2.16 21.465 62.586 21.735 ;
     RECT  2.16 22.005 62.586 22.275 ;
     RECT  2.16 22.545 62.586 22.815 ;
     RECT  2.16 23.085 62.586 23.355 ;
     RECT  2.16 23.625 62.586 23.895 ;
     RECT  2.16 24.165 62.586 24.435 ;
     RECT  2.16 24.705 62.586 24.975 ;
     RECT  2.16 25.245 62.586 25.515 ;
     RECT  2.16 25.785 62.586 26.055 ;
     RECT  2.16 26.325 62.586 26.595 ;
     RECT  2.16 26.865 62.586 27.135 ;
     RECT  2.16 27.405 62.586 27.675 ;
    LAYER RVTP ;
     RECT  2.16 2.295 62.586 2.565 ;
     RECT  2.16 2.835 62.586 3.105 ;
     RECT  2.16 3.375 62.586 3.645 ;
     RECT  2.16 3.915 62.586 4.185 ;
     RECT  2.16 4.455 62.586 4.725 ;
     RECT  2.16 4.995 62.586 5.265 ;
     RECT  2.16 5.535 62.586 5.805 ;
     RECT  2.16 6.075 62.586 6.345 ;
     RECT  2.16 6.615 62.586 6.885 ;
     RECT  2.16 7.155 62.586 7.425 ;
     RECT  2.16 7.695 62.586 7.965 ;
     RECT  2.16 8.235 62.586 8.505 ;
     RECT  2.16 8.775 62.586 9.045 ;
     RECT  2.16 9.315 62.586 9.585 ;
     RECT  2.16 9.855 62.586 10.125 ;
     RECT  2.16 10.395 62.586 10.665 ;
     RECT  2.16 10.935 62.586 11.205 ;
     RECT  2.16 11.475 62.586 11.745 ;
     RECT  2.16 12.015 62.586 12.285 ;
     RECT  2.16 12.555 62.586 12.825 ;
     RECT  2.16 13.095 62.586 13.365 ;
     RECT  2.16 13.635 62.586 13.905 ;
     RECT  2.16 14.175 62.586 14.445 ;
     RECT  2.16 14.715 62.586 14.985 ;
     RECT  2.16 15.255 62.586 15.525 ;
     RECT  2.16 15.795 62.586 16.065 ;
     RECT  2.16 16.335 62.586 16.605 ;
     RECT  2.16 16.875 62.586 17.145 ;
     RECT  2.16 17.415 62.586 17.685 ;
     RECT  2.16 17.955 62.586 18.225 ;
     RECT  2.16 18.495 62.586 18.765 ;
     RECT  2.16 19.035 62.586 19.305 ;
     RECT  2.16 19.575 62.586 19.845 ;
     RECT  2.16 20.115 62.586 20.385 ;
     RECT  2.16 20.655 62.586 20.925 ;
     RECT  2.16 21.195 62.586 21.465 ;
     RECT  2.16 21.735 62.586 22.005 ;
     RECT  2.16 22.275 62.586 22.545 ;
     RECT  2.16 22.815 62.586 23.085 ;
     RECT  2.16 23.355 62.586 23.625 ;
     RECT  2.16 23.895 62.586 24.165 ;
     RECT  2.16 24.435 62.586 24.705 ;
     RECT  2.16 24.975 62.586 25.245 ;
     RECT  2.16 25.515 62.586 25.785 ;
     RECT  2.16 26.055 62.586 26.325 ;
     RECT  2.16 26.595 62.586 26.865 ;
     RECT  2.16 27.135 62.586 27.405 ;
     RECT  2.16 27.675 62.586 27.81 ;
    LAYER M1 ;
     RECT  2.16 2.151 62.586 27.819 ;
    LAYER M2 ;
     RECT  0.103 12.456 0.139 12.474 ;
     RECT  0.139 12.456 2.16 12.78 ;
     RECT  2.16 2.151 18.715 27.819 ;
     RECT  18.715 2.151 19.471 27.864 ;
     RECT  23.935 29.961 23.971 29.979 ;
     RECT  19.471 2.151 24.079 27.936 ;
     RECT  23.971 29.961 24.395 30.168 ;
     RECT  24.395 30.042 24.431 30.168 ;
     RECT  24.079 2.151 24.719 28.476 ;
     RECT  24.719 2.151 25.367 27.936 ;
     RECT  24.431 30.15 25.799 30.168 ;
     RECT  25.591 29.07 26.663 29.088 ;
     RECT  25.367 2.151 28.895 27.9 ;
     RECT  38.767 28.881 38.839 28.899 ;
     RECT  38.839 28.881 38.875 28.944 ;
     RECT  38.875 28.836 39.083 29.052 ;
     RECT  39.083 28.962 39.191 29.052 ;
     RECT  39.191 29.034 39.263 29.052 ;
     RECT  38.263 30.15 39.631 30.168 ;
     RECT  39.631 29.646 39.803 30.168 ;
     RECT  39.803 30.006 39.875 30.168 ;
     RECT  28.895 2.151 39.991 27.819 ;
     RECT  39.991 2.151 40.091 27.972 ;
     RECT  39.875 30.15 40.703 30.168 ;
     RECT  40.495 29.034 40.775 29.052 ;
     RECT  41.287 29.691 41.459 29.709 ;
     RECT  40.091 2.151 41.935 27.819 ;
     RECT  41.647 30.006 42.403 30.168 ;
     RECT  41.935 2.151 42.431 27.972 ;
     RECT  42.403 29.916 42.611 30.168 ;
     RECT  42.611 30.15 43.079 30.168 ;
     RECT  42.431 2.151 62.586 27.819 ;
     RECT  62.586 19.116 62.735 27.324 ;
     RECT  62.735 19.206 62.807 27.324 ;
     RECT  62.807 26.226 63.239 27.324 ;
     RECT  62.586 6.246 63.311 13.824 ;
     RECT  62.807 19.206 63.311 25.434 ;
     RECT  63.311 13.806 63.347 13.824 ;
     RECT  63.311 23.976 63.347 25.344 ;
     RECT  63.239 26.226 63.347 26.784 ;
     RECT  63.347 25.146 63.383 25.164 ;
     RECT  63.347 26.604 63.383 26.784 ;
     RECT  63.311 6.246 63.815 8.028 ;
     RECT  63.311 8.982 63.887 12.654 ;
     RECT  63.311 19.476 63.887 23.148 ;
     RECT  63.347 23.976 63.887 23.994 ;
     RECT  63.383 26.604 63.887 26.622 ;
     RECT  63.815 6.426 63.923 8.028 ;
     RECT  63.887 9.441 63.923 9.459 ;
     RECT  63.887 19.746 63.923 20.106 ;
     RECT  63.887 20.934 63.923 22.23 ;
     RECT  63.923 6.786 63.959 7.218 ;
     RECT  63.923 8.01 63.959 8.028 ;
     RECT  63.887 12.6 63.959 12.618 ;
     RECT  63.923 20.052 63.959 20.106 ;
     RECT  63.923 21.636 63.959 21.654 ;
     RECT  63.959 7.128 63.995 7.218 ;
     RECT  63.995 7.128 64.031 7.146 ;
     RECT  63.959 20.052 64.031 20.07 ;
     RECT  64.651 10.206 64.751 10.224 ;
     RECT  64.651 22.131 64.751 22.149 ;
     RECT  64.651 23.328 64.751 23.346 ;
    LAYER M3 ;
     RECT  2.415 2.143 2.505 2.413 ;
     RECT  5.115 2.143 5.205 2.413 ;
     RECT  7.815 2.143 7.905 2.413 ;
     RECT  10.515 2.143 10.605 2.413 ;
     RECT  13.215 2.143 13.305 2.413 ;
     RECT  15.915 2.143 16.005 2.413 ;
     RECT  18.615 2.143 18.705 2.413 ;
     RECT  21.315 2.143 21.405 2.413 ;
     RECT  24.015 2.143 24.105 2.413 ;
     RECT  26.715 2.143 26.805 2.413 ;
     RECT  29.415 2.143 29.505 2.413 ;
     RECT  32.115 2.143 32.205 2.413 ;
     RECT  34.815 2.143 34.905 2.413 ;
     RECT  37.515 2.143 37.605 2.413 ;
     RECT  40.215 2.143 40.305 2.413 ;
     RECT  42.915 2.143 43.005 2.413 ;
     RECT  45.615 2.143 45.705 2.413 ;
     RECT  48.315 2.143 48.405 2.413 ;
     RECT  51.015 2.143 51.105 2.413 ;
     RECT  53.715 2.143 53.805 2.413 ;
     RECT  56.415 2.143 56.505 2.413 ;
     RECT  59.115 2.143 59.205 2.413 ;
     RECT  61.815 2.143 61.905 2.413 ;
     RECT  48.315 2.413 48.597 2.533 ;
     RECT  48.315 2.533 48.654 2.569 ;
     RECT  48.315 2.569 48.834 2.767 ;
     RECT  47.988 2.767 48.834 2.861 ;
     RECT  45.615 2.413 45.897 2.875 ;
     RECT  51.015 2.413 51.297 2.875 ;
     RECT  52.128 2.803 52.146 2.875 ;
     RECT  45.615 2.875 46.494 2.911 ;
     RECT  51.015 2.875 52.146 2.911 ;
     RECT  45.615 2.911 46.566 3.001 ;
     RECT  42.915 2.413 43.197 3.037 ;
     RECT  50.04 3.019 50.058 3.073 ;
     RECT  50.04 3.073 50.238 3.145 ;
     RECT  51.015 2.911 52.686 3.145 ;
     RECT  42.264 3.037 43.197 3.181 ;
     RECT  45.615 3.001 46.782 3.181 ;
     RECT  50.04 3.145 52.686 3.181 ;
     RECT  53.715 2.413 53.997 3.181 ;
     RECT  45.615 3.181 47.25 3.271 ;
     RECT  42.192 3.181 43.197 3.301 ;
     RECT  50.04 3.181 53.997 3.307 ;
     RECT  44.928 3.271 47.25 3.343 ;
     RECT  49.968 3.307 54.126 3.343 ;
     RECT  55.044 3.271 55.062 3.343 ;
     RECT  49.968 3.343 54.162 3.379 ;
     RECT  54.9 3.343 55.062 3.379 ;
     RECT  49.968 3.379 55.062 3.403 ;
     RECT  48.06 2.861 48.834 3.415 ;
     RECT  41.724 3.301 43.197 3.451 ;
     RECT  44.46 3.343 47.25 3.451 ;
     RECT  48.06 3.415 49.014 3.569 ;
     RECT  49.968 3.403 55.242 3.721 ;
     RECT  56.415 2.413 56.697 3.721 ;
     RECT  49.968 3.721 56.697 3.811 ;
     RECT  41.724 3.451 47.25 3.875 ;
     RECT  40.215 2.413 40.497 3.883 ;
     RECT  39.492 3.883 40.497 3.955 ;
     RECT  41.724 3.875 47.106 3.983 ;
     RECT  39.492 3.955 40.59 3.991 ;
     RECT  41.724 3.983 46.962 3.991 ;
     RECT  48.096 3.569 49.014 3.991 ;
     RECT  49.788 3.811 56.697 3.991 ;
     RECT  37.515 2.413 37.797 4.261 ;
     RECT  48.096 3.991 56.697 4.351 ;
     RECT  37.515 4.261 37.818 4.387 ;
     RECT  39.492 3.991 46.962 4.387 ;
     RECT  39.42 4.387 46.962 4.459 ;
     RECT  39.384 4.459 46.962 4.495 ;
     RECT  37.08 4.387 37.818 4.531 ;
     RECT  48.024 4.351 56.697 4.531 ;
     RECT  37.08 4.531 38.142 4.648 ;
     RECT  39.348 4.495 46.962 4.648 ;
     RECT  48.024 4.531 57.042 4.657 ;
     RECT  48.024 4.657 57.546 4.693 ;
     RECT  47.916 4.693 57.546 4.765 ;
     RECT  37.08 4.648 46.962 4.801 ;
     RECT  47.916 4.765 57.942 4.919 ;
     RECT  37.08 4.801 47.106 5.027 ;
     RECT  37.08 5.027 38.502 5.035 ;
     RECT  52.56 4.919 57.942 5.071 ;
     RECT  39.348 5.027 47.106 5.269 ;
     RECT  47.916 4.919 51.786 5.269 ;
     RECT  36.576 5.035 38.502 5.341 ;
     RECT  52.56 5.071 58.302 5.515 ;
     RECT  59.115 2.413 59.397 5.515 ;
     RECT  39.348 5.269 51.786 5.737 ;
     RECT  52.56 5.515 59.397 5.737 ;
     RECT  36.18 5.341 38.502 5.845 ;
     RECT  39.348 5.737 59.397 5.873 ;
     RECT  36.18 5.845 38.574 5.881 ;
     RECT  39.348 5.873 49.446 5.881 ;
     RECT  36.18 5.881 49.446 6.232 ;
     RECT  61.815 2.413 62.097 6.241 ;
     RECT  34.815 2.413 35.097 6.349 ;
     RECT  35.892 6.232 49.446 6.349 ;
     RECT  61.092 6.241 62.097 6.385 ;
     RECT  60.3 5.575 60.318 6.421 ;
     RECT  61.056 6.385 62.097 6.421 ;
     RECT  63.792 6.241 63.81 6.421 ;
     RECT  32.115 2.413 32.397 6.547 ;
     RECT  50.22 5.873 59.397 6.547 ;
     RECT  50.22 6.547 59.454 6.583 ;
     RECT  60.3 6.421 62.097 6.583 ;
     RECT  50.22 6.583 62.097 6.655 ;
     RECT  33.624 6.655 33.642 6.691 ;
     RECT  34.815 6.349 49.446 6.691 ;
     RECT  50.22 6.655 62.73 6.691 ;
     RECT  32.115 6.547 32.706 6.781 ;
     RECT  33.624 6.691 62.73 6.781 ;
     RECT  63.792 6.421 63.918 6.781 ;
     RECT  31.428 6.781 32.706 6.817 ;
     RECT  33.552 6.781 62.73 6.817 ;
     RECT  31.428 6.817 62.73 6.881 ;
     RECT  50.688 6.881 62.73 7.051 ;
     RECT  63.792 6.781 63.954 7.051 ;
     RECT  50.688 7.051 63.954 7.123 ;
     RECT  50.688 7.123 64.026 7.259 ;
     RECT  50.688 7.259 60.57 7.349 ;
     RECT  61.416 7.259 64.026 7.373 ;
     RECT  29.415 2.413 29.697 7.387 ;
     RECT  29.415 7.387 30.042 7.501 ;
     RECT  29.415 7.501 30.402 7.591 ;
     RECT  31.428 6.881 49.914 7.591 ;
     RECT  28.584 7.591 28.602 7.735 ;
     RECT  28.476 7.735 28.602 7.861 ;
     RECT  29.415 7.591 49.914 7.861 ;
     RECT  50.688 7.349 60.426 7.861 ;
     RECT  26.715 2.413 26.997 7.897 ;
     RECT  28.008 7.861 28.602 7.897 ;
     RECT  26.715 7.897 28.602 7.949 ;
     RECT  63.288 7.373 64.026 7.949 ;
     RECT  27.72 7.949 28.602 8.005 ;
     RECT  29.415 7.861 60.426 8.005 ;
     RECT  27.72 8.005 60.426 8.159 ;
     RECT  27.72 8.159 58.122 8.195 ;
     RECT  58.86 8.159 60.426 8.195 ;
     RECT  59.115 8.195 60.426 8.203 ;
     RECT  61.416 7.373 62.19 8.203 ;
     RECT  63.288 7.949 63.954 8.203 ;
     RECT  59.115 8.203 63.954 8.429 ;
     RECT  61.776 8.429 63.954 8.717 ;
     RECT  27.936 8.195 58.122 8.771 ;
     RECT  59.115 8.429 60.966 9.053 ;
     RECT  27.936 8.771 33.606 9.067 ;
     RECT  61.776 8.717 63.918 9.247 ;
     RECT  26.715 7.949 26.997 9.391 ;
     RECT  27.792 9.067 33.606 9.391 ;
     RECT  34.344 8.771 58.122 9.391 ;
     RECT  59.115 9.053 60.642 9.391 ;
     RECT  61.74 9.247 63.918 9.391 ;
     RECT  2.415 2.413 2.697 9.547 ;
     RECT  2.415 9.547 3.042 9.625 ;
     RECT  4.212 9.595 4.23 9.625 ;
     RECT  5.115 2.413 5.397 9.625 ;
     RECT  0.54 9.547 0.558 9.677 ;
     RECT  2.376 9.625 3.474 9.691 ;
     RECT  21.315 2.413 21.597 9.751 ;
     RECT  26.715 9.391 33.606 9.751 ;
     RECT  34.344 9.391 60.642 9.751 ;
     RECT  24.015 2.413 24.297 9.787 ;
     RECT  2.304 9.691 3.474 9.859 ;
     RECT  4.212 9.625 5.397 9.859 ;
     RECT  26.715 9.751 60.642 9.859 ;
     RECT  61.452 9.391 63.918 9.869 ;
     RECT  18.615 2.413 18.897 9.931 ;
     RECT  6.804 9.859 6.822 9.959 ;
     RECT  18.615 9.931 19.062 10.049 ;
     RECT  18.615 10.049 18.99 10.093 ;
     RECT  2.304 9.859 5.397 10.109 ;
     RECT  18.072 10.093 18.99 10.121 ;
     RECT  26.388 9.859 60.642 10.171 ;
     RECT  26.208 10.171 60.642 10.193 ;
     RECT  2.304 10.109 3.33 10.201 ;
     RECT  64.728 10.171 64.746 10.201 ;
     RECT  4.284 10.109 5.397 10.205 ;
     RECT  4.284 10.205 4.302 10.229 ;
     RECT  64.656 10.201 64.746 10.229 ;
     RECT  2.232 10.201 3.33 10.253 ;
     RECT  64.656 10.229 64.674 10.253 ;
     RECT  2.304 10.253 3.33 10.319 ;
     RECT  2.304 10.319 2.697 10.355 ;
     RECT  32.115 10.193 60.642 10.363 ;
     RECT  61.452 9.869 63.882 10.363 ;
     RECT  6.228 10.555 6.246 10.625 ;
     RECT  32.115 10.363 63.882 10.637 ;
     RECT  23.364 9.787 24.297 10.699 ;
     RECT  6.444 10.741 6.462 10.829 ;
     RECT  22.824 10.699 24.297 10.829 ;
     RECT  26.208 10.193 31.266 11.011 ;
     RECT  32.115 10.637 55.494 11.011 ;
     RECT  7.815 2.413 8.097 11.128 ;
     RECT  9.108 11.101 9.126 11.165 ;
     RECT  26.208 11.011 55.494 11.245 ;
     RECT  7.815 11.128 8.298 11.365 ;
     RECT  56.268 10.637 63.882 11.399 ;
     RECT  7.815 11.365 8.406 11.405 ;
     RECT  7.815 11.405 8.19 11.453 ;
     RECT  25.884 11.245 55.494 11.515 ;
     RECT  56.268 11.399 60.966 11.515 ;
     RECT  25.236 11.515 60.966 11.669 ;
     RECT  26.172 11.669 60.966 11.789 ;
     RECT  10.515 2.413 10.797 11.995 ;
     RECT  23.364 10.829 24.297 12.091 ;
     RECT  56.415 11.789 60.966 12.209 ;
     RECT  10.296 11.995 10.797 12.245 ;
     RECT  61.776 11.399 63.882 12.289 ;
     RECT  23.256 12.091 24.297 12.325 ;
     RECT  10.515 12.245 10.797 12.361 ;
     RECT  12.132 12.181 12.15 12.361 ;
     RECT  61.74 12.289 63.882 12.427 ;
     RECT  12.132 12.361 12.33 12.478 ;
     RECT  0.108 9.739 0.162 12.479 ;
     RECT  10.515 12.361 10.854 12.479 ;
     RECT  12.132 12.478 12.366 12.515 ;
     RECT  22.752 12.325 24.297 12.517 ;
     RECT  25.236 11.669 25.254 12.517 ;
     RECT  26.172 11.789 55.602 12.523 ;
     RECT  56.415 12.209 60.102 12.523 ;
     RECT  61.74 12.427 63.954 12.623 ;
     RECT  22.752 12.517 25.254 12.631 ;
     RECT  60.876 12.209 60.966 12.631 ;
     RECT  61.74 12.623 63.882 12.631 ;
     RECT  12.348 12.515 12.366 12.659 ;
     RECT  60.876 12.631 63.882 12.659 ;
     RECT  0.144 12.479 0.162 12.785 ;
     RECT  21.096 9.751 21.597 12.829 ;
     RECT  21.096 12.829 21.654 12.901 ;
     RECT  22.464 12.631 25.254 12.901 ;
     RECT  21.096 12.901 25.254 12.991 ;
     RECT  26.172 12.523 60.102 12.991 ;
     RECT  21.096 12.991 60.102 13.055 ;
     RECT  21.096 13.055 57.114 13.063 ;
     RECT  17.136 12.901 17.154 13.091 ;
     RECT  58.176 13.055 60.102 13.091 ;
     RECT  18.072 10.121 18.897 13.171 ;
     RECT  60.876 12.659 63.342 13.199 ;
     RECT  21.06 13.063 57.114 13.559 ;
     RECT  61.74 13.199 63.342 13.559 ;
     RECT  61.74 13.559 62.097 13.595 ;
     RECT  19.908 12.487 19.926 13.711 ;
     RECT  18.072 13.171 18.954 13.819 ;
     RECT  19.764 13.711 20.106 13.819 ;
     RECT  63.324 13.559 63.342 13.829 ;
     RECT  26.172 13.559 57.114 13.837 ;
     RECT  17.532 13.819 20.106 13.981 ;
     RECT  21.06 13.559 25.254 13.981 ;
     RECT  26.172 13.837 57.438 13.981 ;
     RECT  58.176 13.091 59.886 13.981 ;
     RECT  26.172 13.981 59.886 14.107 ;
     RECT  60.732 13.441 60.75 14.107 ;
     RECT  17.532 13.981 25.254 14.207 ;
     RECT  17.532 14.207 17.55 14.243 ;
     RECT  18.288 14.207 25.254 14.243 ;
     RECT  26.172 14.107 60.75 14.449 ;
     RECT  26.172 14.449 60.93 14.755 ;
     RECT  26.064 14.755 60.93 15.061 ;
     RECT  26.064 15.061 61.002 15.067 ;
     RECT  61.815 13.595 62.097 15.067 ;
     RECT  26.064 15.067 62.097 15.251 ;
     RECT  18.615 14.243 25.254 15.389 ;
     RECT  19.908 15.389 25.254 15.421 ;
     RECT  26.064 15.251 58.122 15.421 ;
     RECT  19.908 15.421 58.122 15.997 ;
     RECT  58.932 15.251 62.097 15.997 ;
     RECT  19.908 15.997 62.097 16.141 ;
     RECT  19.908 16.141 62.19 16.403 ;
     RECT  19.908 16.403 62.097 17.645 ;
     RECT  18.615 15.389 18.897 17.947 ;
     RECT  19.908 17.645 22.806 17.947 ;
     RECT  18.615 17.947 22.806 18.023 ;
     RECT  23.58 17.645 62.097 18.149 ;
     RECT  23.58 18.149 61.074 18.185 ;
     RECT  19.908 18.023 22.806 18.221 ;
     RECT  23.58 18.185 60.966 18.463 ;
     RECT  20.628 18.221 22.806 18.491 ;
     RECT  20.772 18.491 22.806 18.571 ;
     RECT  23.544 18.463 60.966 18.571 ;
     RECT  20.772 18.571 60.966 18.689 ;
     RECT  21.315 18.689 60.966 18.761 ;
     RECT  22.68 18.761 60.966 18.995 ;
     RECT  61.815 18.149 62.097 19.111 ;
     RECT  61.815 19.111 62.73 19.201 ;
     RECT  22.68 18.995 27.09 19.229 ;
     RECT  27.936 18.995 60.966 19.265 ;
     RECT  57.816 19.265 60.966 19.345 ;
     RECT  61.815 19.201 63.306 19.345 ;
     RECT  57.816 19.345 63.306 19.471 ;
     RECT  57.816 19.471 63.882 19.741 ;
     RECT  27.936 19.265 57.006 20.011 ;
     RECT  57.816 19.741 63.918 20.011 ;
     RECT  27.936 20.011 63.918 20.047 ;
     RECT  22.68 19.229 26.997 20.119 ;
     RECT  22.68 20.119 27.126 20.155 ;
     RECT  21.315 18.761 21.597 20.281 ;
     RECT  22.68 20.155 27.162 20.281 ;
     RECT  21.315 20.281 27.162 20.461 ;
     RECT  27.936 20.047 64.026 20.461 ;
     RECT  21.315 20.461 64.026 20.717 ;
     RECT  21.315 20.717 63.918 20.965 ;
     RECT  21.276 20.965 63.918 21.029 ;
     RECT  61.56 21.029 63.918 21.389 ;
     RECT  63.288 21.389 63.918 21.631 ;
     RECT  21.276 21.029 60.534 21.703 ;
     RECT  20.952 21.703 60.534 21.739 ;
     RECT  20.916 21.739 60.534 21.775 ;
     RECT  20.232 21.775 60.534 21.811 ;
     RECT  18.615 18.023 18.897 21.931 ;
     RECT  63.288 21.631 63.954 21.965 ;
     RECT  18.615 21.931 19.422 22.081 ;
     RECT  20.196 21.811 60.534 22.081 ;
     RECT  64.728 22.075 64.746 22.12 ;
     RECT  64.656 22.12 64.746 22.154 ;
     RECT  64.656 22.154 64.674 22.157 ;
     RECT  18.615 22.081 60.534 22.243 ;
     RECT  61.56 21.389 62.097 22.243 ;
     RECT  18.615 22.243 62.097 22.279 ;
     RECT  63.288 21.965 63.918 22.279 ;
     RECT  18.615 22.279 63.918 22.349 ;
     RECT  64.656 23.275 64.674 23.323 ;
     RECT  64.656 23.323 64.746 23.351 ;
     RECT  18.615 22.349 63.882 23.357 ;
     RECT  64.728 23.351 64.746 23.36 ;
     RECT  18.615 23.357 59.397 23.701 ;
     RECT  18.468 23.701 59.397 23.827 ;
     RECT  60.156 23.357 63.882 23.927 ;
     RECT  60.228 23.927 63.882 24.077 ;
     RECT  18.288 23.827 59.397 24.241 ;
     RECT  18.288 24.241 59.49 24.709 ;
     RECT  60.228 24.077 63.342 24.709 ;
     RECT  18.288 24.709 63.342 25.141 ;
     RECT  18.288 25.141 63.378 25.241 ;
     RECT  18.288 25.241 55.278 25.555 ;
     RECT  56.124 25.241 63.378 25.867 ;
     RECT  17.928 25.555 55.278 25.979 ;
     RECT  17.928 25.979 54.126 26.015 ;
     RECT  17.928 26.015 33.786 26.087 ;
     RECT  17.928 26.087 33.714 26.095 ;
     RECT  17.784 26.095 33.714 26.123 ;
     RECT  56.124 25.867 63.882 26.357 ;
     RECT  54.936 25.979 55.278 26.491 ;
     RECT  56.124 26.357 62.19 26.491 ;
     RECT  63.18 26.357 63.882 26.627 ;
     RECT  17.784 26.123 33.606 26.635 ;
     RECT  34.524 26.015 54.126 26.779 ;
     RECT  54.936 26.491 62.19 26.779 ;
     RECT  63.18 26.627 63.378 26.789 ;
     RECT  34.524 26.779 62.19 26.861 ;
     RECT  17.568 26.635 33.606 26.941 ;
     RECT  34.524 26.861 54.702 26.941 ;
     RECT  55.476 26.861 62.19 27.059 ;
     RECT  63.18 26.789 63.234 27.059 ;
     RECT  56.088 27.059 60.462 27.131 ;
     RECT  17.568 26.941 54.702 27.203 ;
     RECT  61.776 27.059 62.097 27.203 ;
     RECT  17.568 27.203 51.297 27.329 ;
     RECT  52.488 27.203 54.702 27.329 ;
     RECT  56.16 27.131 60.462 27.329 ;
     RECT  63.216 27.059 63.234 27.329 ;
     RECT  17.568 27.329 35.406 27.337 ;
     RECT  17.46 27.337 35.406 27.341 ;
     RECT  57.564 27.329 59.397 27.341 ;
     RECT  31.032 27.341 35.406 27.365 ;
     RECT  50.184 27.329 50.202 27.365 ;
     RECT  53.208 27.329 54.522 27.365 ;
     RECT  60.444 27.329 60.462 27.365 ;
     RECT  32.115 27.365 33.57 27.473 ;
     RECT  34.74 27.365 35.334 27.509 ;
     RECT  58.248 27.341 59.397 27.509 ;
     RECT  2.415 10.355 2.697 27.557 ;
     RECT  5.115 10.205 5.397 27.557 ;
     RECT  7.815 11.453 8.097 27.557 ;
     RECT  10.515 12.479 10.797 27.557 ;
     RECT  13.215 2.413 13.497 27.557 ;
     RECT  15.915 2.413 16.197 27.557 ;
     RECT  32.115 27.473 32.85 27.557 ;
     RECT  37.515 27.329 44.586 27.557 ;
     RECT  51.015 27.329 51.297 27.557 ;
     RECT  59.115 27.509 59.397 27.557 ;
     RECT  61.815 27.203 62.097 27.557 ;
     RECT  17.46 27.341 30.114 27.599 ;
     RECT  31.068 27.365 31.302 27.599 ;
     RECT  32.307 27.557 32.85 27.599 ;
     RECT  34.74 27.509 35.154 27.599 ;
     RECT  36.36 27.329 36.522 27.599 ;
     RECT  37.548 27.557 44.586 27.599 ;
     RECT  45.324 27.329 49.446 27.599 ;
     RECT  58.248 27.509 58.374 27.599 ;
     RECT  17.46 27.599 29.898 27.635 ;
     RECT  32.307 27.599 32.706 27.635 ;
     RECT  36.36 27.599 36.378 27.635 ;
     RECT  45.504 27.599 48.597 27.635 ;
     RECT  56.304 27.329 56.697 27.635 ;
     RECT  58.248 27.599 58.266 27.635 ;
     RECT  34.74 27.599 35.097 27.671 ;
     RECT  46.764 27.635 48.597 27.671 ;
     RECT  17.46 27.635 29.718 27.677 ;
     RECT  31.068 27.599 31.086 27.68 ;
     RECT  47.808 27.671 48.597 27.707 ;
     RECT  53.208 27.365 53.997 27.707 ;
     RECT  17.46 27.677 27.63 27.715 ;
     RECT  17.316 27.715 27.63 27.743 ;
     RECT  28.8 27.677 29.718 27.743 ;
     RECT  37.548 27.599 44.226 27.743 ;
     RECT  17.316 27.743 26.997 27.779 ;
     RECT  37.548 27.743 43.197 27.779 ;
     RECT  44.208 27.743 44.226 27.779 ;
     RECT  45.504 27.635 45.897 27.779 ;
     RECT  46.764 27.671 46.782 27.779 ;
     RECT  2.607 27.557 2.697 27.827 ;
     RECT  5.307 27.557 5.397 27.827 ;
     RECT  8.007 27.557 8.097 27.827 ;
     RECT  10.707 27.557 10.797 27.827 ;
     RECT  13.407 27.557 13.497 27.827 ;
     RECT  16.107 27.557 16.197 27.827 ;
     RECT  21.24 27.779 26.997 27.827 ;
     RECT  28.872 27.743 29.697 27.827 ;
     RECT  32.307 27.635 32.397 27.827 ;
     RECT  35.007 27.671 35.097 27.827 ;
     RECT  37.707 27.779 43.197 27.827 ;
     RECT  45.807 27.779 45.897 27.827 ;
     RECT  48.507 27.707 48.597 27.827 ;
     RECT  51.207 27.557 51.297 27.827 ;
     RECT  53.907 27.707 53.997 27.827 ;
     RECT  56.607 27.635 56.697 27.827 ;
     RECT  59.307 27.557 59.397 27.827 ;
     RECT  62.007 27.557 62.097 27.827 ;
     RECT  17.316 27.779 20.502 27.869 ;
     RECT  21.24 27.827 26.694 27.869 ;
     RECT  22.32 27.869 22.914 27.905 ;
     RECT  28.872 27.827 28.89 27.905 ;
     RECT  21.24 27.869 21.402 27.917 ;
     RECT  21.312 27.917 21.402 27.941 ;
     RECT  22.32 27.905 22.842 27.941 ;
     RECT  17.316 27.869 19.494 28.445 ;
     RECT  17.568 28.445 19.494 28.493 ;
     RECT  23.976 27.869 26.658 29.093 ;
     RECT  18.216 28.493 18.234 29.117 ;
     RECT  23.976 29.093 26.19 29.956 ;
     RECT  38.268 27.827 43.074 30.173 ;
     RECT  23.94 29.956 26.19 30.204 ;
     RECT  38.34 30.173 42.894 30.204 ;
    LAYER M4 ;
     RECT  0.06 9.36 0.227 10.248 ;
     RECT  0.227 9.456 0.371 10.248 ;
     RECT  0.371 9.552 0.421 10.248 ;
     RECT  0.421 9.552 2.408 10.296 ;
     RECT  0.325 15.552 2.408 15.576 ;
     RECT  0.181 16.608 2.408 16.632 ;
     RECT  2.408 2.148 2.512 27.552 ;
     RECT  2.512 2.418 2.6 27.552 ;
     RECT  2.6 2.418 2.704 27.822 ;
     RECT  2.704 9.552 3.053 9.864 ;
     RECT  3.053 9.84 3.697 9.864 ;
     RECT  3.697 9.84 4.201 10.104 ;
     RECT  4.201 9.6 4.273 10.104 ;
     RECT  4.273 9.6 5.108 10.2 ;
     RECT  2.704 15.552 5.108 15.576 ;
     RECT  2.704 16.608 5.108 16.632 ;
     RECT  5.108 2.148 5.212 27.552 ;
     RECT  5.212 2.418 5.3 27.552 ;
     RECT  5.3 2.418 5.404 27.822 ;
     RECT  5.404 9.6 6.227 11.16 ;
     RECT  6.227 10.08 6.805 11.16 ;
     RECT  6.805 10.08 7.808 11.448 ;
     RECT  5.404 15.552 7.808 15.576 ;
     RECT  5.404 16.608 7.808 16.632 ;
     RECT  7.808 2.148 7.912 27.552 ;
     RECT  7.912 2.418 8 27.552 ;
     RECT  8 2.418 8.104 27.822 ;
     RECT  8.104 10.08 10.508 10.104 ;
     RECT  8.104 11.136 10.508 12.024 ;
     RECT  8.104 15.552 10.508 15.576 ;
     RECT  8.104 16.608 10.508 16.632 ;
     RECT  10.508 2.148 10.612 27.552 ;
     RECT  10.612 2.418 10.7 27.552 ;
     RECT  10.7 2.418 10.804 27.822 ;
     RECT  10.804 10.08 13.208 10.104 ;
     RECT  10.804 11.136 13.208 11.16 ;
     RECT  10.804 15.552 13.208 15.576 ;
     RECT  10.804 16.608 13.208 16.632 ;
     RECT  13.208 2.148 13.312 27.552 ;
     RECT  13.312 2.418 13.4 27.552 ;
     RECT  13.4 2.418 13.504 27.822 ;
     RECT  13.504 10.08 15.908 10.104 ;
     RECT  13.504 11.136 15.908 11.16 ;
     RECT  13.504 15.552 15.908 15.576 ;
     RECT  13.504 16.608 15.908 16.632 ;
     RECT  15.908 2.148 16.012 27.552 ;
     RECT  16.012 2.418 16.1 27.552 ;
     RECT  16.1 2.418 16.204 27.822 ;
     RECT  16.204 26.544 16.933 27.822 ;
     RECT  16.933 26.544 17.221 27.912 ;
     RECT  17.221 26.544 17.989 28.488 ;
     RECT  17.989 26.304 18.133 28.488 ;
     RECT  18.133 25.632 18.205 28.488 ;
     RECT  18.205 25.632 18.323 29.112 ;
     RECT  18.323 25.632 18.601 28.488 ;
     RECT  16.204 10.08 18.608 10.104 ;
     RECT  16.204 11.136 18.608 11.16 ;
     RECT  17.521 13.824 18.608 13.848 ;
     RECT  16.204 15.552 18.608 15.576 ;
     RECT  16.204 16.608 18.608 16.632 ;
     RECT  18.601 25.536 18.608 28.488 ;
     RECT  18.608 2.148 18.712 28.488 ;
     RECT  18.712 2.418 18.904 28.488 ;
     RECT  18.904 25.296 19.043 28.488 ;
     RECT  18.853 30.048 19.043 30.072 ;
     RECT  18.904 10.08 19.187 11.16 ;
     RECT  18.904 13.392 19.379 14.28 ;
     RECT  19.043 25.488 19.505 28.488 ;
     RECT  18.904 16.608 19.964 16.632 ;
     RECT  18.904 17.952 19.964 17.976 ;
     RECT  18.904 15.36 20.005 15.576 ;
     RECT  19.964 16.608 20.005 17.976 ;
     RECT  20.005 15.36 20.051 17.976 ;
     RECT  19.505 25.488 20.365 27.912 ;
     RECT  18.904 21.936 21.013 22.248 ;
     RECT  20.051 17.952 21.157 17.976 ;
     RECT  20.365 25.2 21.269 27.912 ;
     RECT  19.187 10.704 21.308 11.16 ;
     RECT  19.379 13.392 21.308 13.416 ;
     RECT  20.051 15.36 21.308 16.632 ;
     RECT  21.157 17.952 21.308 18.168 ;
     RECT  21.013 21.936 21.308 22.776 ;
     RECT  20.401 23.904 21.308 23.928 ;
     RECT  21.269 25.2 21.308 27.822 ;
     RECT  21.308 2.148 21.412 27.822 ;
     RECT  21.412 2.418 21.604 27.822 ;
     RECT  21.604 21.408 21.809 27.72 ;
     RECT  21.604 13.296 22.061 13.416 ;
     RECT  21.604 15.456 22.601 18.168 ;
     RECT  22.601 15.456 22.673 17.976 ;
     RECT  21.809 21.408 22.777 27.432 ;
     RECT  22.777 20.496 22.787 27.432 ;
     RECT  21.604 10.8 22.813 11.16 ;
     RECT  22.673 15.456 22.817 17.064 ;
     RECT  22.787 20.496 23.033 22.2 ;
     RECT  22.813 10.704 23.365 11.16 ;
     RECT  22.787 23.616 23.389 27.432 ;
     RECT  22.061 13.296 23.533 13.32 ;
     RECT  23.533 13.152 23.605 13.32 ;
     RECT  23.605 13.104 23.677 13.656 ;
     RECT  23.389 23.616 23.749 27.528 ;
     RECT  23.677 12.528 23.785 13.656 ;
     RECT  22.817 15.456 23.785 16.632 ;
     RECT  23.033 21.504 23.893 22.2 ;
     RECT  23.749 23.376 23.893 27.528 ;
     RECT  23.365 10.704 24.008 11.496 ;
     RECT  23.785 12.528 24.008 16.632 ;
     RECT  23.033 20.496 24.008 20.52 ;
     RECT  23.893 21.504 24.008 27.528 ;
     RECT  24.008 2.148 24.112 27.552 ;
     RECT  24.112 2.418 24.2 27.552 ;
     RECT  24.217 29.664 24.289 29.688 ;
     RECT  24.2 2.418 24.304 27.822 ;
     RECT  24.304 12.528 24.437 16.872 ;
     RECT  24.289 29.664 24.572 29.784 ;
     RECT  24.437 12.528 24.617 14.04 ;
     RECT  24.572 29.664 24.649 30.12 ;
     RECT  24.437 15.264 24.797 16.872 ;
     RECT  24.617 12.528 24.844 13.608 ;
     RECT  24.304 21.552 24.901 27.822 ;
     RECT  24.797 15.264 24.905 16.632 ;
     RECT  24.901 21.552 24.905 27.912 ;
     RECT  24.649 29.664 25.091 30.168 ;
     RECT  24.844 12.816 25.121 13.608 ;
     RECT  25.091 29.712 25.667 30.168 ;
     RECT  25.667 30 26.029 30.168 ;
     RECT  24.905 21.552 26.089 22.104 ;
     RECT  26.029 30 26.099 30.12 ;
     RECT  24.905 15.552 26.125 16.632 ;
     RECT  26.099 30 26.147 30.024 ;
     RECT  24.304 10.704 26.197 11.496 ;
     RECT  24.905 23.28 26.237 27.912 ;
     RECT  26.089 21.12 26.305 22.248 ;
     RECT  26.237 23.28 26.305 27.864 ;
     RECT  26.053 19.776 26.54 19.8 ;
     RECT  26.305 21.12 26.54 27.864 ;
     RECT  26.54 19.776 26.633 27.864 ;
     RECT  26.197 10.176 26.708 11.544 ;
     RECT  25.121 12.816 26.708 13.32 ;
     RECT  26.125 15.552 26.708 17.208 ;
     RECT  26.633 19.776 26.708 27.822 ;
     RECT  26.708 2.148 26.812 27.822 ;
     RECT  26.812 2.418 27.004 27.822 ;
     RECT  27.004 19.776 27.101 27.72 ;
     RECT  27.004 10.176 27.209 13.32 ;
     RECT  27.004 15.36 27.395 17.784 ;
     RECT  27.101 19.776 27.587 20.568 ;
     RECT  27.004 18.768 27.613 18.792 ;
     RECT  27.587 20.544 27.628 20.568 ;
     RECT  27.395 15.36 27.641 15.768 ;
     RECT  27.101 21.6 27.641 27.72 ;
     RECT  27.004 7.92 27.731 7.944 ;
     RECT  27.004 9.072 28.037 9.096 ;
     RECT  27.209 10.272 28.037 13.32 ;
     RECT  27.395 16.752 28.141 17.784 ;
     RECT  27.641 15.456 28.289 15.768 ;
     RECT  28.141 16.752 28.397 17.976 ;
     RECT  27.641 21.6 28.573 27.672 ;
     RECT  28.397 16.752 28.597 17.16 ;
     RECT  28.573 21.552 28.645 27.672 ;
     RECT  28.037 10.656 28.933 13.32 ;
     RECT  28.289 15.456 29.269 15.576 ;
     RECT  28.933 10.656 29.408 14.232 ;
     RECT  29.269 15.216 29.408 15.576 ;
     RECT  28.597 16.608 29.408 17.16 ;
     RECT  28.465 19.536 29.408 19.56 ;
     RECT  28.645 20.592 29.408 27.672 ;
     RECT  29.408 2.148 29.512 27.672 ;
     RECT  29.512 2.418 29.6 27.672 ;
     RECT  29.6 2.418 29.704 27.822 ;
     RECT  29.704 19.536 29.837 27.672 ;
     RECT  29.704 9.648 29.843 16.632 ;
     RECT  29.837 20.016 29.981 27.672 ;
     RECT  29.704 7.392 30.053 8.424 ;
     RECT  29.704 17.952 30.733 17.976 ;
     RECT  30.733 17.616 30.769 17.976 ;
     RECT  30.053 7.92 30.845 8.424 ;
     RECT  29.843 9.792 30.877 16.632 ;
     RECT  29.981 20.016 30.913 20.472 ;
     RECT  30.845 8.4 30.917 8.424 ;
     RECT  30.877 9.6 30.949 16.632 ;
     RECT  30.769 17.616 30.949 18.312 ;
     RECT  30.913 19.344 31.025 20.472 ;
     RECT  29.981 21.744 31.097 27.672 ;
     RECT  30.949 9.6 31.129 18.312 ;
     RECT  31.025 19.344 31.129 19.368 ;
     RECT  31.097 21.744 31.309 27.192 ;
     RECT  31.025 20.4 31.333 20.472 ;
     RECT  31.309 21.504 31.333 27.192 ;
     RECT  31.129 9.6 31.957 19.368 ;
     RECT  31.957 9.168 32.108 19.368 ;
     RECT  31.333 20.4 32.108 27.192 ;
     RECT  32.108 2.148 32.212 27.552 ;
     RECT  32.212 2.418 32.3 27.552 ;
     RECT  32.3 2.418 32.404 27.822 ;
     RECT  32.404 9.6 32.645 13.32 ;
     RECT  32.404 14.832 33.113 17.496 ;
     RECT  32.404 7.488 33.257 7.512 ;
     RECT  33.113 14.88 33.401 17.496 ;
     RECT  32.404 19.296 33.445 27.192 ;
     RECT  33.445 18.768 33.517 27.192 ;
     RECT  32.645 9.888 33.541 13.32 ;
     RECT  33.517 18.768 33.617 19.368 ;
     RECT  33.517 20.4 33.617 27.192 ;
     RECT  33.617 20.4 33.725 26.088 ;
     RECT  33.541 9.888 34.441 13.608 ;
     RECT  33.401 15.36 34.549 17.496 ;
     RECT  33.617 18.816 34.621 19.368 ;
     RECT  33.725 20.4 34.621 21.72 ;
     RECT  34.621 18.816 34.765 21.72 ;
     RECT  33.725 22.8 34.765 26.088 ;
     RECT  33.613 6.672 34.808 6.696 ;
     RECT  34.441 8.976 34.808 13.608 ;
     RECT  34.549 15.36 34.808 17.688 ;
     RECT  34.765 18.816 34.808 26.088 ;
     RECT  33.617 27.072 34.808 27.192 ;
     RECT  34.808 2.148 34.912 27.552 ;
     RECT  34.912 2.418 35 27.552 ;
     RECT  35 2.418 35.104 27.822 ;
     RECT  35.104 18.816 35.219 18.84 ;
     RECT  35.104 15.408 35.309 17.256 ;
     RECT  35.309 15.408 35.363 16.632 ;
     RECT  35.104 19.872 35.417 27.192 ;
     RECT  35.104 8.448 35.993 8.472 ;
     RECT  35.104 9.84 36.097 13.608 ;
     RECT  36.097 9.552 36.349 13.608 ;
     RECT  35.104 6.24 36.385 7.368 ;
     RECT  36.349 9.552 36.385 13.704 ;
     RECT  36.385 9.552 36.457 14.28 ;
     RECT  35.363 15.552 36.457 16.632 ;
     RECT  36.457 9.552 36.805 16.632 ;
     RECT  36.385 6.24 36.997 7.416 ;
     RECT  36.997 6.24 37.141 7.656 ;
     RECT  36.805 8.88 37.141 16.632 ;
     RECT  35.417 19.872 37.333 27.096 ;
     RECT  37.141 6.24 37.393 16.632 ;
     RECT  37.069 4.656 37.508 4.68 ;
     RECT  37.393 6 37.508 16.632 ;
     RECT  36.673 18.768 37.508 18.792 ;
     RECT  37.333 19.872 37.508 27.192 ;
     RECT  37.508 2.148 37.612 27.552 ;
     RECT  37.612 2.418 37.7 27.552 ;
     RECT  37.7 2.418 37.804 27.822 ;
     RECT  37.804 4.656 38.153 13.944 ;
     RECT  37.804 18.768 38.189 27.768 ;
     RECT  38.189 18.768 38.297 18.792 ;
     RECT  38.189 19.776 38.297 27.768 ;
     RECT  38.401 29.664 38.473 29.688 ;
     RECT  38.473 29.664 38.557 29.784 ;
     RECT  38.297 19.872 38.579 27.768 ;
     RECT  38.579 19.872 38.585 27.384 ;
     RECT  38.153 4.656 38.873 7.752 ;
     RECT  38.557 29.664 38.977 29.736 ;
     RECT  38.153 8.784 39.013 13.944 ;
     RECT  37.804 15.216 39.013 17.448 ;
     RECT  38.977 29.04 39.125 29.736 ;
     RECT  39.013 8.784 39.161 17.448 ;
     RECT  39.125 29.664 39.553 29.736 ;
     RECT  38.585 19.872 39.637 27.336 ;
     RECT  39.161 15.456 39.661 17.448 ;
     RECT  39.637 19.872 39.925 27.768 ;
     RECT  39.925 19.872 40.067 28.104 ;
     RECT  38.873 5.088 40.208 7.752 ;
     RECT  39.161 8.784 40.208 13.944 ;
     RECT  39.661 15.456 40.208 17.688 ;
     RECT  40.067 19.872 40.208 28.008 ;
     RECT  40.208 2.148 40.259 28.008 ;
     RECT  40.259 2.148 40.312 27.96 ;
     RECT  40.312 2.418 40.504 27.96 ;
     RECT  40.504 4.656 40.565 5.208 ;
     RECT  40.504 18.72 40.565 27.96 ;
     RECT  39.553 29.664 41.027 30.168 ;
     RECT  40.565 18.72 41.557 27.72 ;
     RECT  40.504 6.336 41.569 16.536 ;
     RECT  41.557 18.72 41.645 27.768 ;
     RECT  41.701 3.312 41.788 3.336 ;
     RECT  41.645 18.72 41.932 27.336 ;
     RECT  41.932 18.72 41.989 26.856 ;
     RECT  40.565 4.656 42.037 4.68 ;
     RECT  41.989 18.192 42.145 26.856 ;
     RECT  42.037 4.656 42.217 5.112 ;
     RECT  42.217 4.368 42.289 5.112 ;
     RECT  41.569 6.24 42.289 16.536 ;
     RECT  41.027 29.664 42.361 29.784 ;
     RECT  42.361 29.664 42.509 30.168 ;
     RECT  42.145 18.048 42.757 26.856 ;
     RECT  42.509 29.664 42.761 29.688 ;
     RECT  42.289 4.368 42.793 16.584 ;
     RECT  42.757 17.616 42.793 26.856 ;
     RECT  42.793 4.368 42.908 26.856 ;
     RECT  42.908 2.148 43.012 27.552 ;
     RECT  43.012 2.418 43.1 27.552 ;
     RECT  43.1 2.418 43.204 27.822 ;
     RECT  43.204 3.936 43.379 5.304 ;
     RECT  43.204 6.336 43.841 27.384 ;
     RECT  43.841 7.68 43.955 27.384 ;
     RECT  43.955 9.12 44.021 27.384 ;
     RECT  44.021 9.12 44.129 16.104 ;
     RECT  43.379 4.128 44.197 5.304 ;
     RECT  43.841 6.336 44.197 6.696 ;
     RECT  44.197 4.128 44.449 6.696 ;
     RECT  44.129 9.216 44.525 16.104 ;
     RECT  44.449 3.408 44.561 6.696 ;
     RECT  44.561 4.992 44.989 6.696 ;
     RECT  43.955 7.68 44.989 8.04 ;
     RECT  44.525 9.264 45.025 16.104 ;
     RECT  45.025 9.264 45.133 16.344 ;
     RECT  44.021 17.664 45.133 27.384 ;
     RECT  44.561 3.408 45.608 3.432 ;
     RECT  44.989 4.992 45.608 8.04 ;
     RECT  45.133 9.264 45.608 27.384 ;
     RECT  45.608 2.148 45.712 27.552 ;
     RECT  45.712 2.418 45.8 27.552 ;
     RECT  45.8 2.418 45.904 27.822 ;
     RECT  45.904 3.408 46.001 8.04 ;
     RECT  46.001 3.408 46.019 5.352 ;
     RECT  45.904 17.424 46.109 26.808 ;
     RECT  46.109 17.472 46.115 26.808 ;
     RECT  45.904 9.264 46.145 16.344 ;
     RECT  46.145 9.312 46.181 16.344 ;
     RECT  46.019 3.408 46.253 5.304 ;
     RECT  46.115 17.664 46.325 26.808 ;
     RECT  46.325 17.664 46.361 26.328 ;
     RECT  46.361 18 46.397 26.328 ;
     RECT  46.397 18 46.973 18.84 ;
     RECT  46.253 3.936 47.005 5.304 ;
     RECT  46.001 6.336 47.005 7.752 ;
     RECT  47.005 3.936 47.117 7.752 ;
     RECT  46.181 9.312 47.153 16.104 ;
     RECT  46.397 19.872 47.545 26.328 ;
     RECT  46.973 18.816 47.653 18.84 ;
     RECT  47.545 19.872 47.653 27.192 ;
     RECT  47.153 9.312 47.833 15.816 ;
     RECT  47.977 2.832 48.044 2.856 ;
     RECT  47.689 16.848 48.049 16.872 ;
     RECT  48.044 2.832 48.308 3.528 ;
     RECT  47.117 4.896 48.308 7.752 ;
     RECT  47.833 8.832 48.308 15.816 ;
     RECT  48.049 16.848 48.308 16.92 ;
     RECT  47.653 18.816 48.308 27.192 ;
     RECT  48.308 2.148 48.412 27.552 ;
     RECT  48.412 2.418 48.5 27.552 ;
     RECT  48.5 2.418 48.604 27.822 ;
     RECT  48.604 18.816 49.241 27.336 ;
     RECT  48.604 15.312 49.349 17.64 ;
     RECT  49.849 3.936 49.957 3.96 ;
     RECT  48.604 7.68 49.993 14.184 ;
     RECT  49.349 15.312 49.993 15.672 ;
     RECT  49.349 16.8 49.993 17.64 ;
     RECT  49.241 18.816 49.993 26.904 ;
     RECT  49.957 3.552 50.029 3.96 ;
     RECT  48.604 5.232 50.065 6.648 ;
     RECT  49.993 7.68 50.065 15.672 ;
     RECT  50.029 3.024 51.008 3.96 ;
     RECT  50.065 5.232 51.008 15.672 ;
     RECT  49.993 16.8 51.008 26.904 ;
     RECT  51.008 2.148 51.112 27.552 ;
     RECT  51.112 2.418 51.2 27.552 ;
     RECT  51.2 2.418 51.304 27.822 ;
     RECT  51.304 5.28 51.779 18.84 ;
     RECT  51.779 5.28 51.82 7.8 ;
     RECT  51.779 8.976 51.869 18.84 ;
     RECT  51.304 3.024 52.013 3.048 ;
     RECT  51.869 8.976 52.157 14.232 ;
     RECT  51.869 15.216 52.297 18.84 ;
     RECT  51.304 19.872 52.297 26.952 ;
     RECT  51.82 5.28 52.405 7.752 ;
     RECT  52.405 4.416 53.341 7.752 ;
     RECT  52.157 8.976 53.341 14.136 ;
     RECT  53.341 4.416 53.557 14.136 ;
     RECT  52.297 15.216 53.557 26.952 ;
     RECT  53.701 3.408 53.708 3.432 ;
     RECT  53.557 4.416 53.708 26.952 ;
     RECT  53.708 2.148 53.812 27.552 ;
     RECT  53.812 2.418 53.9 27.552 ;
     RECT  53.9 2.418 54.004 27.822 ;
     RECT  54.004 3.408 54.131 17.496 ;
     RECT  54.131 3.408 54.209 14.952 ;
     RECT  54.209 3.408 54.353 14.856 ;
     RECT  54.131 15.936 54.569 17.496 ;
     RECT  54.569 15.936 54.605 17.4 ;
     RECT  54.004 20.4 54.641 27.096 ;
     RECT  54.004 18.72 55.037 19.272 ;
     RECT  54.353 9.312 55.249 14.856 ;
     RECT  54.353 3.408 55.253 7.896 ;
     RECT  55.253 4.272 55.325 7.896 ;
     RECT  55.069 19.344 55.532 19.368 ;
     RECT  54.641 20.4 55.532 26.904 ;
     RECT  55.325 5.04 55.669 7.896 ;
     RECT  55.669 5.04 55.897 8.28 ;
     RECT  55.249 9.312 55.897 14.952 ;
     RECT  54.605 15.936 56.069 16.872 ;
     RECT  55.897 5.04 56.408 14.952 ;
     RECT  56.069 15.936 56.408 17.16 ;
     RECT  55.669 18.192 56.408 18.216 ;
     RECT  55.532 19.344 56.408 26.904 ;
     RECT  56.408 2.148 56.512 27.552 ;
     RECT  56.512 2.418 56.6 27.552 ;
     RECT  56.6 2.418 56.704 27.822 ;
     RECT  56.704 5.04 57.341 7.992 ;
     RECT  56.704 20.16 57.629 27.336 ;
     RECT  56.704 16.032 57.635 19.128 ;
     RECT  57.629 21.024 57.635 27.336 ;
     RECT  57.635 18.528 57.665 19.128 ;
     RECT  56.704 9.072 57.773 12.792 ;
     RECT  57.665 18.816 57.773 19.128 ;
     RECT  57.773 9.072 57.845 11.544 ;
     RECT  57.635 21.12 57.889 27.336 ;
     RECT  56.704 14.352 57.953 14.952 ;
     RECT  57.341 5.28 57.989 7.992 ;
     RECT  57.889 21.408 58.061 27.336 ;
     RECT  57.773 12.768 58.22 12.792 ;
     RECT  57.953 14.352 58.22 14.712 ;
     RECT  57.989 5.52 58.741 7.992 ;
     RECT  58.741 5.52 58.844 8.04 ;
     RECT  57.845 9.072 58.844 11.16 ;
     RECT  58.22 12.768 59.065 14.712 ;
     RECT  58.844 5.52 59.108 11.16 ;
     RECT  59.065 12.528 59.108 14.712 ;
     RECT  57.635 16.032 59.108 17.448 ;
     RECT  57.829 19.584 59.108 19.608 ;
     RECT  58.061 21.408 59.108 26.232 ;
     RECT  58.061 27.312 59.108 27.336 ;
     RECT  59.108 2.148 59.212 27.552 ;
     RECT  59.212 2.418 59.3 27.552 ;
     RECT  59.3 2.418 59.404 27.822 ;
     RECT  59.404 7.392 59.465 12.552 ;
     RECT  59.465 7.68 59.609 11.688 ;
     RECT  59.404 14.112 59.609 17.448 ;
     RECT  59.609 14.112 59.753 17.4 ;
     RECT  59.404 21.408 59.753 26.136 ;
     RECT  59.609 7.68 59.788 9.096 ;
     RECT  59.609 10.128 59.843 11.688 ;
     RECT  59.753 14.112 59.861 17.352 ;
     RECT  59.753 21.984 59.891 26.136 ;
     RECT  59.788 7.68 60.113 8.04 ;
     RECT  59.861 16.656 60.113 17.352 ;
     RECT  60.113 7.68 60.149 7.704 ;
     RECT  60.113 16.656 60.293 17.112 ;
     RECT  59.843 10.128 60.365 11.4 ;
     RECT  59.861 14.112 60.365 15.096 ;
     RECT  60.365 10.176 60.401 11.4 ;
     RECT  59.891 21.984 60.467 25.8 ;
     RECT  60.467 24.432 60.653 25.8 ;
     RECT  60.653 24.432 60.689 24.984 ;
     RECT  59.788 9.024 61.808 9.096 ;
     RECT  60.401 10.176 61.808 11.016 ;
     RECT  60.365 15.072 61.808 15.096 ;
     RECT  60.293 16.656 61.808 16.68 ;
     RECT  60.757 20.976 61.808 21 ;
     RECT  60.467 21.984 61.808 23.352 ;
     RECT  60.689 24.432 61.808 24.456 ;
     RECT  61.808 2.148 61.912 27.552 ;
     RECT  61.912 2.418 62 27.552 ;
     RECT  62 2.418 62.104 27.822 ;
     RECT  62.104 7.344 63.277 7.368 ;
     RECT  62.104 8.4 63.277 12.744 ;
     RECT  62.104 20.112 63.277 25.8 ;
     RECT  63.277 7.344 63.313 12.84 ;
     RECT  63.277 19.92 63.349 25.8 ;
     RECT  63.313 7.344 63.781 12.936 ;
     RECT  63.781 7.248 63.817 12.936 ;
     RECT  63.817 6.864 64.716 12.936 ;
     RECT  63.349 19.92 64.716 25.992 ;
     RECT  64.716 10.176 64.757 10.2 ;
     RECT  64.716 22.08 64.757 22.104 ;
     RECT  64.716 23.328 64.757 23.352 ;
    LAYER M5 ;
     RECT  2.4 2.137 2.52 2.151 ;
     RECT  5.1 2.137 5.22 2.151 ;
     RECT  7.8 2.137 7.92 2.151 ;
     RECT  10.5 2.137 10.62 2.151 ;
     RECT  13.2 2.137 13.32 2.151 ;
     RECT  15.9 2.137 16.02 2.151 ;
     RECT  18.6 2.137 18.72 2.151 ;
     RECT  21.3 2.137 21.42 2.151 ;
     RECT  24 2.137 24.12 2.151 ;
     RECT  26.7 2.137 26.82 2.151 ;
     RECT  29.4 2.137 29.52 2.151 ;
     RECT  32.1 2.137 32.22 2.151 ;
     RECT  34.8 2.137 34.92 2.151 ;
     RECT  37.5 2.137 37.62 2.151 ;
     RECT  40.2 2.137 40.32 2.151 ;
     RECT  42.9 2.137 43.02 2.151 ;
     RECT  45.6 2.137 45.72 2.151 ;
     RECT  48.3 2.137 48.42 2.151 ;
     RECT  51 2.137 51.12 2.151 ;
     RECT  53.7 2.137 53.82 2.151 ;
     RECT  56.4 2.137 56.52 2.151 ;
     RECT  59.1 2.137 59.22 2.151 ;
     RECT  61.8 2.137 61.92 2.151 ;
     RECT  48.3 2.151 48.612 2.821 ;
     RECT  45.6 2.151 45.912 3.397 ;
     RECT  53.7 2.151 54.012 3.397 ;
     RECT  42.9 2.151 43.212 3.925 ;
     RECT  53.7 3.397 54.264 4.115 ;
     RECT  37.5 2.151 37.812 4.645 ;
     RECT  42.9 3.925 43.368 4.645 ;
     RECT  41.712 3.301 41.736 4.691 ;
     RECT  42.72 4.645 43.368 4.691 ;
     RECT  48.096 2.821 48.612 4.931 ;
     RECT  45.6 3.397 46.008 4.981 ;
     RECT  37.5 4.645 38.76 5.123 ;
     RECT  42.72 4.691 43.212 5.171 ;
     RECT  45.504 4.981 46.008 5.363 ;
     RECT  52.704 5.605 52.728 5.749 ;
     RECT  53.7 4.115 54.012 5.749 ;
     RECT  37.5 5.123 37.812 6.229 ;
     RECT  45.504 5.363 45.912 6.229 ;
     RECT  59.1 2.151 59.412 6.229 ;
     RECT  52.704 5.749 54.012 6.323 ;
     RECT  42.9 5.171 43.212 6.613 ;
     RECT  44.256 5.797 44.28 6.613 ;
     RECT  42.9 6.613 44.28 6.659 ;
     RECT  34.8 2.151 35.112 6.661 ;
     RECT  53.52 6.323 54.012 6.709 ;
     RECT  53.52 6.709 54.36 6.803 ;
     RECT  37.5 6.229 37.992 6.805 ;
     RECT  58.848 6.229 59.412 6.851 ;
     RECT  34.8 6.661 35.928 7.091 ;
     RECT  42.9 6.659 43.944 7.381 ;
     RECT  53.7 6.803 54.36 7.475 ;
     RECT  58.896 6.851 59.412 7.669 ;
     RECT  51 2.151 51.312 7.765 ;
     RECT  56.4 2.151 56.712 7.765 ;
     RECT  57.792 6.805 57.816 7.859 ;
     RECT  26.7 2.151 27.012 7.909 ;
     RECT  42.144 7.381 43.944 8.003 ;
     RECT  56.016 7.765 56.712 8.245 ;
     RECT  48.3 4.931 48.612 8.293 ;
     RECT  58.896 7.669 59.736 8.435 ;
     RECT  51 7.765 51.768 8.531 ;
     RECT  42.9 8.003 43.944 8.819 ;
     RECT  37.152 6.805 37.992 8.869 ;
     RECT  36.816 8.869 37.992 9.061 ;
     RECT  26.7 7.909 27.72 9.107 ;
     RECT  32.1 2.151 32.412 9.157 ;
     RECT  0.192 9.349 0.216 9.445 ;
     RECT  0.192 9.445 0.36 9.541 ;
     RECT  55.68 8.245 56.712 9.541 ;
     RECT  5.1 2.151 5.412 9.589 ;
     RECT  48.3 8.293 49.224 9.589 ;
     RECT  29.4 2.151 29.712 9.637 ;
     RECT  31.968 9.157 32.412 9.637 ;
     RECT  48.192 9.589 49.224 9.637 ;
     RECT  47.28 9.637 49.224 9.731 ;
     RECT  36.816 9.061 38.808 9.779 ;
     RECT  58.896 8.435 59.412 9.781 ;
     RECT  51 8.531 51.312 9.925 ;
     RECT  18.6 2.151 18.912 10.069 ;
     RECT  55.344 9.541 56.712 10.115 ;
     RECT  38.784 9.779 38.808 10.211 ;
     RECT  47.28 9.731 48.612 10.211 ;
     RECT  42.9 8.819 43.32 10.213 ;
     RECT  58.32 9.781 59.412 10.213 ;
     RECT  0.192 9.541 0.456 10.307 ;
     RECT  40.2 2.151 40.512 10.405 ;
     RECT  48.192 10.211 48.612 10.451 ;
     RECT  50.88 9.925 51.312 10.453 ;
     RECT  34.8 7.091 35.112 10.693 ;
     RECT  5.1 9.589 6.216 10.789 ;
     RECT  7.8 2.151 8.112 10.789 ;
     RECT  42.9 10.213 44.136 11.075 ;
     RECT  24 2.151 24.312 11.125 ;
     RECT  58.32 10.213 59.832 11.125 ;
     RECT  5.1 10.789 8.112 11.171 ;
     RECT  29.4 9.637 29.832 11.171 ;
     RECT  6.816 11.171 8.112 11.365 ;
     RECT  23.376 11.125 24.312 11.365 ;
     RECT  45.36 6.229 45.912 11.365 ;
     RECT  31.344 9.637 32.412 11.413 ;
     RECT  6.816 11.365 8.424 11.459 ;
     RECT  36.816 9.779 37.812 11.459 ;
     RECT  55.344 10.115 55.368 11.459 ;
     RECT  31.344 11.413 32.664 11.461 ;
     RECT  23.376 11.365 24.792 11.507 ;
     RECT  34.656 10.693 35.112 11.651 ;
     RECT  31.2 11.461 32.664 11.699 ;
     RECT  50.88 10.453 52.008 11.699 ;
     RECT  58.272 11.125 59.832 11.699 ;
     RECT  45.36 11.365 46.728 11.747 ;
     RECT  55.296 11.509 55.32 11.845 ;
     RECT  45.36 11.747 46.296 11.893 ;
     RECT  7.8 11.459 8.424 12.035 ;
     RECT  39.504 10.405 40.512 12.229 ;
     RECT  29.4 11.171 29.712 12.373 ;
     RECT  23.712 11.507 24.792 12.755 ;
     RECT  44.88 11.893 46.296 12.755 ;
     RECT  34.8 11.651 35.112 12.997 ;
     RECT  31.2 11.699 32.412 13.045 ;
     RECT  33.504 12.517 33.528 13.045 ;
     RECT  31.2 13.045 33.528 13.091 ;
     RECT  39.168 12.229 40.512 13.091 ;
     RECT  53.7 7.475 54.12 13.093 ;
     RECT  31.344 13.091 33.528 13.187 ;
     RECT  50.88 11.699 51.312 13.331 ;
     RECT  18.6 10.069 19.176 13.381 ;
     RECT  36.912 11.459 37.812 13.429 ;
     RECT  44.88 12.755 45.912 13.621 ;
     RECT  55.248 11.845 55.32 13.763 ;
     RECT  42.9 11.075 43.32 13.861 ;
     RECT  44.64 13.621 45.912 13.861 ;
     RECT  55.296 13.763 55.32 14.053 ;
     RECT  56.4 10.115 56.712 14.053 ;
     RECT  29.4 12.373 30.12 14.243 ;
     RECT  18.6 13.381 19.368 14.291 ;
     RECT  36.432 13.429 37.812 14.291 ;
     RECT  55.296 14.053 56.712 14.291 ;
     RECT  31.344 13.187 33.384 14.675 ;
     RECT  51 13.331 51.312 14.773 ;
     RECT  53.568 13.093 54.12 14.963 ;
     RECT  29.4 14.243 29.712 15.205 ;
     RECT  36.912 14.291 37.812 15.205 ;
     RECT  48.3 10.451 48.612 15.301 ;
     RECT  42.9 13.861 45.912 15.347 ;
     RECT  51 14.773 51.672 15.347 ;
     RECT  26.7 9.107 27.012 15.349 ;
     RECT  36.912 15.205 38.424 15.443 ;
     RECT  48.3 15.301 49.032 15.443 ;
     RECT  23.76 12.755 24.792 15.445 ;
     RECT  0.192 10.307 0.36 15.587 ;
     RECT  23.76 15.445 24.888 15.587 ;
     RECT  53.7 14.963 54.12 15.587 ;
     RECT  37.056 15.443 38.424 15.683 ;
     RECT  31.68 14.675 33.384 15.781 ;
     RECT  34.8 12.997 35.352 15.781 ;
     RECT  31.68 15.781 35.352 15.971 ;
     RECT  26.7 15.349 27.384 15.973 ;
     RECT  37.296 15.683 38.424 16.019 ;
     RECT  23.76 15.587 24.792 16.259 ;
     RECT  44.64 15.347 45.912 16.309 ;
     RECT  21.3 2.151 21.612 16.357 ;
     RECT  31.68 15.971 35.112 16.499 ;
     RECT  51 15.347 51.312 16.501 ;
     RECT  39.504 13.091 40.512 16.595 ;
     RECT  29.28 15.205 29.712 16.597 ;
     RECT  0.192 15.587 0.216 16.643 ;
     RECT  31.968 16.499 35.112 16.739 ;
     RECT  28.608 16.597 29.712 16.787 ;
     RECT  31.968 16.739 33.384 16.835 ;
     RECT  51 16.501 52.296 16.981 ;
     RECT  53.7 15.587 54.012 16.981 ;
     RECT  26.16 15.973 27.384 17.075 ;
     RECT  55.488 14.291 56.712 17.077 ;
     RECT  29.28 16.787 29.712 17.123 ;
     RECT  21.3 16.357 22.248 17.171 ;
     RECT  26.16 17.075 27.012 17.219 ;
     RECT  55.488 17.077 57.096 17.219 ;
     RECT  42.9 15.347 43.212 17.605 ;
     RECT  34.56 16.739 35.112 17.699 ;
     RECT  39.84 16.595 40.512 17.699 ;
     RECT  20.016 15.973 20.04 17.987 ;
     RECT  42.768 17.605 43.212 18.181 ;
     RECT  55.488 17.219 56.712 18.181 ;
     RECT  58.272 11.699 59.412 18.181 ;
     RECT  44.64 16.309 46.104 18.515 ;
     RECT  51 16.981 54.012 18.659 ;
     RECT  39.984 17.699 40.512 18.709 ;
     RECT  42 18.181 43.212 18.709 ;
     RECT  26.7 17.219 27.012 18.757 ;
     RECT  32.1 16.835 33.384 18.757 ;
     RECT  34.8 17.699 35.112 18.805 ;
     RECT  52.848 18.659 54.012 19.043 ;
     RECT  32.1 18.757 33.48 19.333 ;
     RECT  44.784 18.515 46.104 19.427 ;
     RECT  51 18.659 51.312 19.525 ;
     RECT  55.488 18.181 59.412 19.619 ;
     RECT  39.984 18.709 43.212 19.909 ;
     RECT  50.736 19.525 51.312 20.149 ;
     RECT  23.76 16.259 24.312 20.485 ;
     RECT  55.488 19.619 57.864 20.485 ;
     RECT  48.3 15.443 48.612 20.533 ;
     RECT  26.7 18.757 27.576 20.579 ;
     RECT  34.8 18.805 35.208 20.579 ;
     RECT  26.7 20.579 27.012 20.581 ;
     RECT  29.4 17.123 29.712 20.581 ;
     RECT  55.44 20.485 57.864 20.629 ;
     RECT  31.344 19.333 33.48 20.677 ;
     RECT  44.784 19.427 46.008 21.109 ;
     RECT  31.344 20.677 33.672 21.155 ;
     RECT  39.984 19.909 43.704 21.155 ;
     RECT  50.112 20.149 51.312 21.155 ;
     RECT  55.392 20.629 57.864 21.155 ;
     RECT  23.376 20.485 24.312 21.539 ;
     RECT  23.76 21.539 24.312 21.541 ;
     RECT  37.5 16.019 37.812 21.541 ;
     RECT  44.784 21.109 46.152 21.541 ;
     RECT  28.656 20.581 29.712 21.589 ;
     RECT  32.1 21.155 33.672 21.683 ;
     RECT  26.592 20.581 27.012 21.827 ;
     RECT  37.5 21.541 38.232 21.925 ;
     RECT  47.424 20.533 48.612 21.971 ;
     RECT  53.568 19.043 54.012 21.973 ;
     RECT  55.392 21.155 57.672 22.117 ;
     RECT  53.136 21.973 54.012 22.163 ;
     RECT  32.1 21.683 33.384 22.355 ;
     RECT  39.984 21.155 43.212 22.453 ;
     RECT  55.296 22.117 57.672 22.499 ;
     RECT  34.8 20.579 35.112 22.741 ;
     RECT  39.984 22.453 43.32 22.981 ;
     RECT  34.8 22.741 35.208 23.125 ;
     RECT  37.5 21.925 38.424 23.317 ;
     RECT  50.736 21.155 51.312 23.317 ;
     RECT  59.1 19.619 59.412 23.317 ;
     RECT  44.688 21.541 46.152 23.363 ;
     RECT  50.736 23.317 51.432 23.509 ;
     RECT  39.888 22.981 43.32 23.605 ;
     RECT  22.752 21.637 22.776 23.653 ;
     RECT  23.76 21.541 25.272 23.653 ;
     RECT  50.736 23.509 51.816 23.699 ;
     RECT  44.832 23.363 46.152 23.795 ;
     RECT  32.1 22.355 33.288 23.797 ;
     RECT  50.736 23.699 51.432 23.987 ;
     RECT  59.1 23.317 59.544 24.037 ;
     RECT  28.416 21.589 29.712 24.083 ;
     RECT  26.7 21.827 27.012 24.133 ;
     RECT  58.992 24.037 59.544 24.277 ;
     RECT  34.464 23.125 35.208 24.323 ;
     RECT  26.7 24.133 27.288 24.325 ;
     RECT  29.136 24.083 29.712 24.325 ;
     RECT  37.5 23.317 38.76 24.421 ;
     RECT  39.744 23.605 43.32 24.421 ;
     RECT  22.752 23.653 25.272 24.517 ;
     RECT  26.7 24.325 28.056 24.517 ;
     RECT  44.832 23.795 46.008 24.563 ;
     RECT  48.192 21.971 48.612 24.565 ;
     RECT  49.68 22.741 49.704 24.611 ;
     RECT  21.3 17.171 21.612 24.757 ;
     RECT  37.5 24.421 43.32 24.899 ;
     RECT  21.3 24.757 21.72 24.901 ;
     RECT  22.752 24.517 28.056 24.901 ;
     RECT  53.568 22.163 54.012 24.901 ;
     RECT  29.136 24.325 30.12 25.091 ;
     RECT  52.944 24.901 54.012 25.091 ;
     RECT  21.3 24.901 28.056 25.139 ;
     RECT  47.904 24.565 48.612 25.139 ;
     RECT  58.992 24.277 60.456 25.139 ;
     RECT  23.904 25.139 28.056 25.187 ;
     RECT  18.6 14.291 18.912 25.285 ;
     RECT  31.872 23.797 33.288 25.427 ;
     RECT  31.872 25.427 32.904 25.475 ;
     RECT  50.736 23.987 51.312 25.477 ;
     RECT  18.6 25.285 19.032 25.525 ;
     RECT  37.5 24.899 38.472 25.573 ;
     RECT  29.136 25.091 29.712 25.619 ;
     RECT  18.6 25.525 19.368 25.621 ;
     RECT  45.6 24.563 46.008 25.621 ;
     RECT  58.992 25.139 59.88 25.715 ;
     RECT  21.3 25.139 22.776 26.101 ;
     RECT  59.1 25.715 59.88 26.147 ;
     RECT  53.7 25.091 54.012 26.149 ;
     RECT  21.168 26.101 22.776 26.243 ;
     RECT  44.64 25.621 46.008 26.243 ;
     RECT  50.736 25.477 51.576 26.243 ;
     RECT  55.296 22.499 57.576 26.243 ;
     RECT  39.456 24.899 43.32 26.291 ;
     RECT  18.144 25.621 19.368 26.293 ;
     RECT  32.1 25.475 32.904 26.483 ;
     RECT  15.9 2.151 16.212 26.533 ;
     RECT  18 26.293 19.368 26.533 ;
     RECT  23.904 25.187 27.384 26.533 ;
     RECT  37.344 25.573 38.472 26.533 ;
     RECT  39.456 26.291 41.736 26.533 ;
     RECT  15.9 26.533 19.368 26.629 ;
     RECT  29.4 25.619 29.712 26.677 ;
     RECT  22.752 26.243 22.776 26.773 ;
     RECT  23.856 26.533 27.384 26.773 ;
     RECT  42.72 26.291 43.32 26.819 ;
     RECT  44.64 26.243 45.912 26.819 ;
     RECT  53.424 26.149 54.012 26.819 ;
     RECT  55.824 26.243 56.712 26.819 ;
     RECT  22.752 26.773 27.384 26.867 ;
     RECT  29.04 26.677 29.712 26.963 ;
     RECT  22.752 26.867 27.144 27.011 ;
     RECT  34.8 24.323 35.208 27.059 ;
     RECT  21.168 26.243 21.612 27.107 ;
     RECT  37.344 26.533 41.736 27.203 ;
     RECT  37.5 27.203 41.736 27.301 ;
     RECT  42.72 26.819 43.212 27.301 ;
     RECT  22.752 27.011 27.012 27.395 ;
     RECT  15.9 26.629 19.896 27.539 ;
     RECT  23.856 27.395 27.012 27.539 ;
     RECT  2.4 2.151 2.712 27.819 ;
     RECT  5.1 11.171 5.412 27.819 ;
     RECT  7.8 12.035 8.112 27.819 ;
     RECT  10.5 2.151 10.812 27.819 ;
     RECT  13.2 2.151 13.512 27.819 ;
     RECT  15.9 27.539 19.464 27.819 ;
     RECT  21.3 27.107 21.612 27.819 ;
     RECT  24 27.539 27.012 27.819 ;
     RECT  29.4 26.963 29.712 27.819 ;
     RECT  32.1 26.483 32.412 27.819 ;
     RECT  34.8 27.059 35.112 27.819 ;
     RECT  37.5 27.301 43.212 27.819 ;
     RECT  45.6 26.819 45.912 27.819 ;
     RECT  48.3 25.139 48.612 27.819 ;
     RECT  51 26.243 51.312 27.819 ;
     RECT  53.7 26.819 54.012 27.819 ;
     RECT  56.4 26.819 56.712 27.819 ;
     RECT  59.1 26.147 59.412 27.819 ;
     RECT  61.8 2.151 62.112 27.819 ;
     RECT  2.592 27.819 2.712 27.833 ;
     RECT  5.292 27.819 5.412 27.833 ;
     RECT  7.992 27.819 8.112 27.833 ;
     RECT  10.692 27.819 10.812 27.833 ;
     RECT  13.392 27.819 13.512 27.833 ;
     RECT  16.092 27.819 19.464 27.833 ;
     RECT  21.492 27.819 21.612 27.833 ;
     RECT  24.192 27.819 27.012 27.833 ;
     RECT  29.592 27.819 29.712 27.833 ;
     RECT  32.292 27.819 32.412 27.833 ;
     RECT  34.992 27.819 35.112 27.833 ;
     RECT  37.692 27.819 43.212 27.833 ;
     RECT  45.792 27.819 45.912 27.833 ;
     RECT  48.492 27.819 48.612 27.833 ;
     RECT  51.192 27.819 51.312 27.833 ;
     RECT  53.892 27.819 54.012 27.833 ;
     RECT  56.592 27.819 56.712 27.833 ;
     RECT  59.292 27.819 59.412 27.833 ;
     RECT  61.992 27.819 62.112 27.833 ;
     RECT  38.448 27.833 42.744 29.699 ;
     RECT  38.496 29.699 41.592 29.747 ;
     RECT  24.432 27.833 26.136 29.795 ;
     RECT  38.496 29.747 38.52 29.795 ;
     RECT  39.792 29.747 41.496 29.795 ;
     RECT  39.792 29.795 41.016 29.939 ;
     RECT  24.624 29.795 26.136 30.035 ;
     RECT  24.624 30.035 26.088 30.131 ;
     RECT  16.464 27.833 19.464 30.16 ;
     RECT  25.008 30.131 25.992 30.179 ;
     RECT  39.792 29.939 39.912 30.179 ;
     RECT  40.992 29.939 41.016 30.179 ;
  END
END qfd_landh0_128_NE_65x30
END LIBRARY
